VERSION 5.8 ;
BUSBITCHARS "[]" ;
DIVIDERCHAR "/" ;
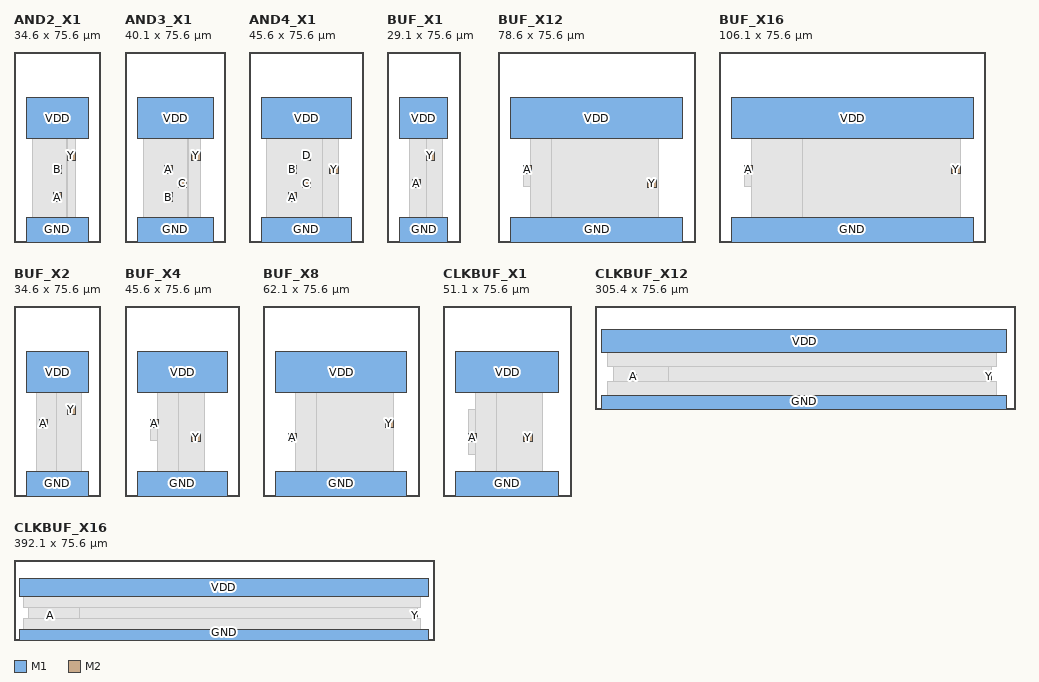
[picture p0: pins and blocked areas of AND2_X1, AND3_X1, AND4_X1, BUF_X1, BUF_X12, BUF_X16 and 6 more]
MACRO AND2_X1
  CLASS CORE ;
  ORIGIN 0 0 ;
  SIZE 34.600 BY 75.600 ;
  SYMMETRY X Y ;
  SITE TR1um_access_site ;
  PIN VDD
    DIRECTION INOUT ;
    USE POWER ;
    PORT
      LAYER M1 ;
        RECT 5.000 41.000 29.600 57.600 ;
    END
  END VDD
  PIN GND
    DIRECTION INOUT ;
    USE GROUND ;
    PORT
      LAYER M1 ;
        RECT 5.000 0.000 29.600 9.800 ;
    END
  END GND
  PIN A
    DIRECTION INPUT ;
    USE SIGNAL ;
    PORT
      LAYER M2 ;
        RECT 15.600 16.100 19.000 19.500 ;
    END
  END A
  PIN B
    DIRECTION INPUT ;
    USE SIGNAL ;
    PORT
      LAYER M2 ;
        RECT 15.600 27.100 19.000 30.500 ;
    END
  END B
  PIN Y
    DIRECTION OUTPUT ;
    USE SIGNAL ;
    PORT
      LAYER M2 ;
        RECT 21.100 32.600 24.500 36.000 ;
    END
  END Y
  OBS
    LAYER M1 ;
      RECT 13.100 6.400 15.700 9.800 ;
    LAYER M1 ;
      RECT 10.600 16.100 19.000 19.500 ;
    LAYER M1 ;
      RECT 14.400 27.100 19.000 35.200 ;
    LAYER M1 ;
      RECT 7.400 6.400 20.900 51.200 ;
    LAYER M1 ;
      RECT 21.100 6.400 24.500 51.200 ;
    LAYER V1 ;
      RECT 16.600 17.100 18.000 18.500 ;
    LAYER V1 ;
      RECT 16.600 28.100 18.000 29.500 ;
    LAYER V1 ;
      RECT 22.100 33.600 23.500 35.000 ;
  END
END AND2_X1
MACRO AND3_X1
  CLASS CORE ;
  ORIGIN 0 0 ;
  SIZE 40.100 BY 75.600 ;
  SYMMETRY X Y ;
  SITE TR1um_access_site ;
  PIN VDD
    DIRECTION INOUT ;
    USE POWER ;
    PORT
      LAYER M1 ;
        RECT 5.000 41.000 35.100 57.600 ;
    END
  END VDD
  PIN GND
    DIRECTION INOUT ;
    USE GROUND ;
    PORT
      LAYER M1 ;
        RECT 5.000 0.000 35.100 9.800 ;
    END
  END GND
  PIN A
    DIRECTION INPUT ;
    USE SIGNAL ;
    PORT
      LAYER M2 ;
        RECT 15.600 27.100 19.000 30.500 ;
    END
  END A
  PIN B
    DIRECTION INPUT ;
    USE SIGNAL ;
    PORT
      LAYER M2 ;
        RECT 15.600 16.100 19.000 19.500 ;
    END
  END B
  PIN C
    DIRECTION INPUT ;
    USE SIGNAL ;
    PORT
      LAYER M2 ;
        RECT 21.100 21.600 24.500 25.000 ;
    END
  END C
  PIN Y
    DIRECTION OUTPUT ;
    USE SIGNAL ;
    PORT
      LAYER M2 ;
        RECT 26.600 32.600 30.000 36.000 ;
    END
  END Y
  OBS
    LAYER M1 ;
      RECT 13.100 6.400 15.700 9.800 ;
    LAYER M1 ;
      RECT 17.100 6.400 19.700 9.800 ;
    LAYER M1 ;
      RECT 12.000 14.600 19.000 19.500 ;
    LAYER M1 ;
      RECT 16.300 21.600 24.500 25.000 ;
    LAYER M1 ;
      RECT 10.700 27.100 19.000 35.800 ;
    LAYER M1 ;
      RECT 7.300 6.400 24.700 51.200 ;
    LAYER M1 ;
      RECT 25.100 6.400 30.000 51.200 ;
    LAYER V1 ;
      RECT 16.600 17.100 18.000 18.500 ;
    LAYER V1 ;
      RECT 22.100 22.600 23.500 24.000 ;
    LAYER V1 ;
      RECT 16.600 28.100 18.000 29.500 ;
    LAYER V1 ;
      RECT 27.600 33.600 29.000 35.000 ;
  END
END AND3_X1
MACRO AND4_X1
  CLASS CORE ;
  ORIGIN 0 0 ;
  SIZE 45.600 BY 75.600 ;
  SYMMETRY X Y ;
  SITE TR1um_access_site ;
  PIN VDD
    DIRECTION INOUT ;
    USE POWER ;
    PORT
      LAYER M1 ;
        RECT 5.000 41.000 40.600 57.600 ;
    END
  END VDD
  PIN GND
    DIRECTION INOUT ;
    USE GROUND ;
    PORT
      LAYER M1 ;
        RECT 5.000 0.000 40.600 9.800 ;
    END
  END GND
  PIN A
    DIRECTION INPUT ;
    USE SIGNAL ;
    PORT
      LAYER M2 ;
        RECT 15.600 16.100 19.000 19.500 ;
    END
  END A
  PIN B
    DIRECTION INPUT ;
    USE SIGNAL ;
    PORT
      LAYER M2 ;
        RECT 15.600 27.100 19.000 30.500 ;
    END
  END B
  PIN C
    DIRECTION INPUT ;
    USE SIGNAL ;
    PORT
      LAYER M2 ;
        RECT 21.100 21.600 24.500 25.000 ;
    END
  END C
  PIN D
    DIRECTION INPUT ;
    USE SIGNAL ;
    PORT
      LAYER M2 ;
        RECT 21.100 32.600 24.500 36.000 ;
    END
  END D
  PIN Y
    DIRECTION OUTPUT ;
    USE SIGNAL ;
    PORT
      LAYER M2 ;
        RECT 32.100 27.100 35.500 30.500 ;
    END
  END Y
  OBS
    LAYER M1 ;
      RECT 13.100 6.400 15.700 9.800 ;
    LAYER M1 ;
      RECT 17.100 6.400 19.700 9.800 ;
    LAYER M1 ;
      RECT 21.100 6.400 23.700 9.800 ;
    LAYER M1 ;
      RECT 10.600 16.100 19.000 23.000 ;
    LAYER M1 ;
      RECT 17.900 21.600 24.500 25.000 ;
    LAYER M1 ;
      RECT 14.400 27.100 19.000 35.200 ;
    LAYER M1 ;
      RECT 21.100 28.400 26.400 36.000 ;
    LAYER M1 ;
      RECT 7.000 6.400 30.500 51.200 ;
    LAYER M1 ;
      RECT 29.100 6.400 35.500 51.200 ;
    LAYER V1 ;
      RECT 16.600 17.100 18.000 18.500 ;
    LAYER V1 ;
      RECT 22.100 22.600 23.500 24.000 ;
    LAYER V1 ;
      RECT 16.600 28.100 18.000 29.500 ;
    LAYER V1 ;
      RECT 33.100 28.100 34.500 29.500 ;
    LAYER V1 ;
      RECT 22.100 33.600 23.500 35.000 ;
  END
END AND4_X1
MACRO BUF_X1
  CLASS CORE ;
  ORIGIN 0 0 ;
  SIZE 29.100 BY 75.600 ;
  SYMMETRY X Y ;
  SITE TR1um_access_site ;
  PIN VDD
    DIRECTION INOUT ;
    USE POWER ;
    PORT
      LAYER M1 ;
        RECT 5.000 41.000 24.100 57.600 ;
    END
  END VDD
  PIN GND
    DIRECTION INOUT ;
    USE GROUND ;
    PORT
      LAYER M1 ;
        RECT 5.000 0.000 24.100 9.800 ;
    END
  END GND
  PIN A
    DIRECTION INPUT ;
    USE SIGNAL ;
    PORT
      LAYER M2 ;
        RECT 10.100 21.600 13.500 25.000 ;
    END
  END A
  PIN Y
    DIRECTION OUTPUT ;
    USE SIGNAL ;
    PORT
      LAYER M2 ;
        RECT 15.600 32.600 19.000 36.000 ;
    END
  END Y
  OBS
    LAYER M1 ;
      RECT 10.100 17.600 14.500 25.000 ;
    LAYER M1 ;
      RECT 9.100 6.400 18.500 51.200 ;
    LAYER M1 ;
      RECT 15.600 6.400 21.900 51.200 ;
    LAYER V1 ;
      RECT 11.100 22.600 12.500 24.000 ;
    LAYER V1 ;
      RECT 16.600 33.600 18.000 35.000 ;
  END
END BUF_X1
MACRO BUF_X12
  CLASS CORE ;
  ORIGIN 0 0 ;
  SIZE 78.600 BY 75.600 ;
  SYMMETRY X Y ;
  SITE TR1um_access_site ;
  PIN VDD
    DIRECTION INOUT ;
    USE POWER ;
    PORT
      LAYER M1 ;
        RECT 5.000 41.000 73.600 57.600 ;
    END
  END VDD
  PIN GND
    DIRECTION INOUT ;
    USE GROUND ;
    PORT
      LAYER M1 ;
        RECT 5.000 0.000 73.600 9.800 ;
    END
  END GND
  PIN A
    DIRECTION INPUT ;
    USE SIGNAL ;
    PORT
      LAYER M2 ;
        RECT 10.100 27.100 13.500 30.500 ;
    END
  END A
  PIN Y
    DIRECTION OUTPUT ;
    USE SIGNAL ;
    PORT
      LAYER M2 ;
        RECT 59.600 21.600 63.000 25.000 ;
    END
  END Y
  OBS
    LAYER M1 ;
      RECT 10.100 22.000 14.500 30.500 ;
    LAYER M1 ;
      RECT 13.100 6.400 59.500 51.200 ;
    LAYER M1 ;
      RECT 21.100 6.400 63.700 51.200 ;
    LAYER V1 ;
      RECT 60.600 22.600 62.000 24.000 ;
    LAYER V1 ;
      RECT 11.100 28.100 12.500 29.500 ;
  END
END BUF_X12
MACRO BUF_X16
  CLASS CORE ;
  ORIGIN 0 0 ;
  SIZE 106.100 BY 75.600 ;
  SYMMETRY X Y ;
  SITE TR1um_access_site ;
  PIN VDD
    DIRECTION INOUT ;
    USE POWER ;
    PORT
      LAYER M1 ;
        RECT 5.000 41.000 101.100 57.600 ;
    END
  END VDD
  PIN GND
    DIRECTION INOUT ;
    USE GROUND ;
    PORT
      LAYER M1 ;
        RECT 5.000 0.000 101.100 9.800 ;
    END
  END GND
  PIN A
    DIRECTION INPUT ;
    USE SIGNAL ;
    PORT
      LAYER M2 ;
        RECT 10.100 27.100 13.500 30.500 ;
    END
  END A
  PIN Y
    DIRECTION OUTPUT ;
    USE SIGNAL ;
    PORT
      LAYER M2 ;
        RECT 92.600 27.100 96.000 30.500 ;
    END
  END Y
  OBS
    LAYER M1 ;
      RECT 10.100 22.000 14.500 30.500 ;
    LAYER M1 ;
      RECT 13.100 6.400 87.700 51.200 ;
    LAYER M1 ;
      RECT 33.100 6.400 96.000 51.200 ;
    LAYER V1 ;
      RECT 11.100 28.100 12.500 29.500 ;
    LAYER V1 ;
      RECT 93.600 28.100 95.000 29.500 ;
  END
END BUF_X16
MACRO BUF_X2
  CLASS CORE ;
  ORIGIN 0 0 ;
  SIZE 34.600 BY 75.600 ;
  SYMMETRY X Y ;
  SITE TR1um_access_site ;
  PIN VDD
    DIRECTION INOUT ;
    USE POWER ;
    PORT
      LAYER M1 ;
        RECT 5.000 41.000 29.600 57.600 ;
    END
  END VDD
  PIN GND
    DIRECTION INOUT ;
    USE GROUND ;
    PORT
      LAYER M1 ;
        RECT 5.000 0.000 29.600 9.800 ;
    END
  END GND
  PIN A
    DIRECTION INPUT ;
    USE SIGNAL ;
    PORT
      LAYER M2 ;
        RECT 10.100 27.100 13.500 30.500 ;
    END
  END A
  PIN Y
    DIRECTION OUTPUT ;
    USE SIGNAL ;
    PORT
      LAYER M2 ;
        RECT 21.100 32.600 24.500 36.000 ;
    END
  END Y
  OBS
    LAYER M1 ;
      RECT 10.100 22.200 14.500 30.500 ;
    LAYER M1 ;
      RECT 9.100 6.400 22.500 51.200 ;
    LAYER M1 ;
      RECT 17.100 6.400 26.900 51.200 ;
    LAYER V1 ;
      RECT 11.100 28.100 12.500 29.500 ;
    LAYER V1 ;
      RECT 22.100 33.600 23.500 35.000 ;
  END
END BUF_X2
MACRO BUF_X4
  CLASS CORE ;
  ORIGIN 0 0 ;
  SIZE 45.600 BY 75.600 ;
  SYMMETRY X Y ;
  SITE TR1um_access_site ;
  PIN VDD
    DIRECTION INOUT ;
    USE POWER ;
    PORT
      LAYER M1 ;
        RECT 5.000 41.000 40.600 57.600 ;
    END
  END VDD
  PIN GND
    DIRECTION INOUT ;
    USE GROUND ;
    PORT
      LAYER M1 ;
        RECT 5.000 0.000 40.600 9.800 ;
    END
  END GND
  PIN A
    DIRECTION INPUT ;
    USE SIGNAL ;
    PORT
      LAYER M2 ;
        RECT 10.100 27.100 13.500 30.500 ;
    END
  END A
  PIN Y
    DIRECTION OUTPUT ;
    USE SIGNAL ;
    PORT
      LAYER M2 ;
        RECT 26.600 21.600 30.000 25.000 ;
    END
  END Y
  OBS
    LAYER M1 ;
      RECT 10.100 22.000 15.400 30.500 ;
    LAYER M1 ;
      RECT 13.100 6.400 22.500 51.200 ;
    LAYER M1 ;
      RECT 21.100 6.400 31.700 51.200 ;
    LAYER V1 ;
      RECT 27.600 22.600 29.000 24.000 ;
    LAYER V1 ;
      RECT 11.100 28.100 12.500 29.500 ;
  END
END BUF_X4
MACRO BUF_X8
  CLASS CORE ;
  ORIGIN 0 0 ;
  SIZE 62.100 BY 75.600 ;
  SYMMETRY X Y ;
  SITE TR1um_access_site ;
  PIN VDD
    DIRECTION INOUT ;
    USE POWER ;
    PORT
      LAYER M1 ;
        RECT 5.000 41.000 57.100 57.600 ;
    END
  END VDD
  PIN GND
    DIRECTION INOUT ;
    USE GROUND ;
    PORT
      LAYER M1 ;
        RECT 5.000 0.000 57.100 9.800 ;
    END
  END GND
  PIN A
    DIRECTION INPUT ;
    USE SIGNAL ;
    PORT
      LAYER M2 ;
        RECT 10.100 21.600 13.500 25.000 ;
    END
  END A
  PIN Y
    DIRECTION OUTPUT ;
    USE SIGNAL ;
    PORT
      LAYER M2 ;
        RECT 48.600 27.100 52.000 30.500 ;
    END
  END Y
  OBS
    LAYER M1 ;
      RECT 10.100 21.600 16.900 25.000 ;
    LAYER M1 ;
      RECT 13.100 6.400 42.500 51.200 ;
    LAYER M1 ;
      RECT 21.100 6.400 52.000 51.200 ;
    LAYER V1 ;
      RECT 11.100 22.600 12.500 24.000 ;
    LAYER V1 ;
      RECT 49.600 28.100 51.000 29.500 ;
  END
END BUF_X8
MACRO CLKBUF_X1
  CLASS CORE ;
  ORIGIN 0 0 ;
  SIZE 51.100 BY 75.600 ;
  SYMMETRY X Y ;
  SITE TR1um_access_site ;
  PIN VDD
    DIRECTION INOUT ;
    USE POWER ;
    PORT
      LAYER M1 ;
        RECT 5.000 41.000 46.100 57.600 ;
    END
  END VDD
  PIN GND
    DIRECTION INOUT ;
    USE GROUND ;
    PORT
      LAYER M1 ;
        RECT 5.000 0.000 46.100 9.800 ;
    END
  END GND
  PIN A
    DIRECTION INPUT ;
    USE SIGNAL ;
    PORT
      LAYER M2 ;
        RECT 10.100 21.600 13.500 25.000 ;
    END
  END A
  PIN Y
    DIRECTION OUTPUT ;
    USE SIGNAL ;
    PORT
      LAYER M2 ;
        RECT 32.100 21.600 35.500 25.000 ;
    END
  END Y
  OBS
    LAYER M1 ;
      RECT 10.100 16.400 15.700 34.400 ;
    LAYER M1 ;
      RECT 13.100 6.400 29.700 51.200 ;
    LAYER M1 ;
      RECT 21.100 6.400 39.700 51.200 ;
    LAYER V1 ;
      RECT 11.100 22.600 12.500 24.000 ;
    LAYER V1 ;
      RECT 33.100 22.600 34.500 24.000 ;
  END
END CLKBUF_X1
MACRO CLKBUF_X12
  CLASS CORE ;
  ORIGIN 0 0 ;
  SIZE 305.400 BY 75.600 ;
  SYMMETRY X Y ;
  SITE TR1um_access_site ;
  PIN VDD
    DIRECTION INOUT ;
    USE POWER ;
    PORT
      LAYER M1 ;
        RECT 5.000 41.000 299.100 57.600 ;
    END
  END VDD
  PIN GND
    DIRECTION INOUT ;
    USE GROUND ;
    PORT
      LAYER M1 ;
        RECT 5.000 0.000 299.100 9.800 ;
    END
  END GND
  PIN A
    DIRECTION INPUT ;
    USE SIGNAL ;
    PORT
      LAYER M2 ;
        RECT 26.600 21.600 30.000 25.000 ;
    END
  END A
  PIN Y
    DIRECTION OUTPUT ;
    USE SIGNAL ;
    PORT
      LAYER M2 ;
        RECT 285.100 21.600 288.500 25.000 ;
    END
  END Y
  OBS
    LAYER M1 ;
      RECT 19.100 16.400 41.700 34.400 ;
    LAYER M1 ;
      RECT 13.100 6.400 281.700 51.200 ;
    LAYER M1 ;
      RECT 53.100 6.400 288.500 51.200 ;
    LAYER V1 ;
      RECT 8.900 4.000 291.900 20.200 ;
    LAYER V1 ;
      RECT 8.900 30.600 291.900 53.600 ;
    LAYER V1 ;
      RECT 164.300 0.000 167.300 2.800 ;
    LAYER V1 ;
      RECT 169.800 0.000 172.800 2.800 ;
    LAYER V1 ;
      RECT 175.300 0.000 178.300 2.800 ;
    LAYER V1 ;
      RECT 180.800 0.000 183.800 2.800 ;
    LAYER V1 ;
      RECT 186.300 0.000 189.300 2.800 ;
    LAYER V1 ;
      RECT 191.800 0.000 194.800 2.800 ;
    LAYER V1 ;
      RECT 197.300 0.000 200.300 2.800 ;
    LAYER V1 ;
      RECT 202.800 0.000 205.800 2.800 ;
    LAYER V1 ;
      RECT 208.300 0.000 211.300 2.800 ;
    LAYER V1 ;
      RECT 213.800 0.000 216.800 2.800 ;
    LAYER V1 ;
      RECT 219.300 0.000 222.300 2.800 ;
    LAYER V1 ;
      RECT 224.800 0.000 227.800 2.800 ;
    LAYER V1 ;
      RECT 230.300 0.000 233.300 2.800 ;
    LAYER V1 ;
      RECT 235.800 0.000 238.800 2.800 ;
    LAYER V1 ;
      RECT 241.300 0.000 244.300 2.800 ;
    LAYER V1 ;
      RECT 246.800 0.000 249.800 2.800 ;
    LAYER V1 ;
      RECT 252.300 0.000 255.300 2.800 ;
    LAYER V1 ;
      RECT 257.800 0.000 260.800 2.800 ;
    LAYER V1 ;
      RECT 263.300 0.000 266.300 2.800 ;
    LAYER V1 ;
      RECT 268.800 0.000 271.800 2.800 ;
    LAYER V1 ;
      RECT 274.300 0.000 277.300 2.800 ;
    LAYER V1 ;
      RECT 279.800 0.000 282.800 2.800 ;
    LAYER V1 ;
      RECT 285.300 0.000 288.300 2.800 ;
    LAYER V1 ;
      RECT 290.800 0.000 293.800 2.800 ;
    LAYER V1 ;
      RECT 296.300 0.000 299.300 2.800 ;
    LAYER V1 ;
      RECT 153.300 0.000 156.300 2.800 ;
    LAYER V1 ;
      RECT 286.100 22.600 287.500 24.000 ;
    LAYER V1 ;
      RECT 158.800 0.000 161.800 2.800 ;
    LAYER V1 ;
      RECT 153.300 54.800 156.300 57.800 ;
    LAYER V1 ;
      RECT 158.800 54.800 161.800 57.800 ;
    LAYER V1 ;
      RECT 164.300 54.800 167.300 57.800 ;
    LAYER V1 ;
      RECT 169.800 54.800 172.800 57.800 ;
    LAYER V1 ;
      RECT 175.300 54.800 178.300 57.800 ;
    LAYER V1 ;
      RECT 180.800 54.800 183.800 57.800 ;
    LAYER V1 ;
      RECT 186.300 54.800 189.300 57.800 ;
    LAYER V1 ;
      RECT 191.800 54.800 194.800 57.800 ;
    LAYER V1 ;
      RECT 197.300 54.800 200.300 57.800 ;
    LAYER V1 ;
      RECT 202.800 54.800 205.800 57.800 ;
    LAYER V1 ;
      RECT 208.300 54.800 211.300 57.800 ;
    LAYER V1 ;
      RECT 213.800 54.800 216.800 57.800 ;
    LAYER V1 ;
      RECT 219.300 54.800 222.300 57.800 ;
    LAYER V1 ;
      RECT 224.800 54.800 227.800 57.800 ;
    LAYER V1 ;
      RECT 230.300 54.800 233.300 57.800 ;
    LAYER V1 ;
      RECT 235.800 54.800 238.800 57.800 ;
    LAYER V1 ;
      RECT 241.300 54.800 244.300 57.800 ;
    LAYER V1 ;
      RECT 246.800 54.800 249.800 57.800 ;
    LAYER V1 ;
      RECT 252.300 54.800 255.300 57.800 ;
    LAYER V1 ;
      RECT 257.800 54.800 260.800 57.800 ;
    LAYER V1 ;
      RECT 263.300 54.800 266.300 57.800 ;
    LAYER V1 ;
      RECT 268.800 54.800 271.800 57.800 ;
    LAYER V1 ;
      RECT 274.300 54.800 277.300 57.800 ;
    LAYER V1 ;
      RECT 279.800 54.800 282.800 57.800 ;
    LAYER V1 ;
      RECT 285.300 54.800 288.300 57.800 ;
    LAYER V1 ;
      RECT 290.800 54.800 293.800 57.800 ;
    LAYER V1 ;
      RECT 296.300 54.800 299.300 57.800 ;
    LAYER V1 ;
      RECT 15.800 0.000 18.800 2.800 ;
    LAYER V1 ;
      RECT 4.800 54.800 7.800 57.800 ;
    LAYER V1 ;
      RECT 10.300 54.800 13.300 57.800 ;
    LAYER V1 ;
      RECT 15.800 54.800 18.800 57.800 ;
    LAYER V1 ;
      RECT 21.300 54.800 24.300 57.800 ;
    LAYER V1 ;
      RECT 26.800 54.800 29.800 57.800 ;
    LAYER V1 ;
      RECT 32.300 54.800 35.300 57.800 ;
    LAYER V1 ;
      RECT 37.800 54.800 40.800 57.800 ;
    LAYER V1 ;
      RECT 43.300 54.800 46.300 57.800 ;
    LAYER V1 ;
      RECT 48.800 54.800 51.800 57.800 ;
    LAYER V1 ;
      RECT 54.300 54.800 57.300 57.800 ;
    LAYER V1 ;
      RECT 59.800 54.800 62.800 57.800 ;
    LAYER V1 ;
      RECT 65.300 54.800 68.300 57.800 ;
    LAYER V1 ;
      RECT 70.800 54.800 73.800 57.800 ;
    LAYER V1 ;
      RECT 76.300 54.800 79.300 57.800 ;
    LAYER V1 ;
      RECT 81.800 54.800 84.800 57.800 ;
    LAYER V1 ;
      RECT 87.300 54.800 90.300 57.800 ;
    LAYER V1 ;
      RECT 92.800 54.800 95.800 57.800 ;
    LAYER V1 ;
      RECT 98.300 54.800 101.300 57.800 ;
    LAYER V1 ;
      RECT 103.800 54.800 106.800 57.800 ;
    LAYER V1 ;
      RECT 109.300 54.800 112.300 57.800 ;
    LAYER V1 ;
      RECT 114.800 54.800 117.800 57.800 ;
    LAYER V1 ;
      RECT 120.300 54.800 123.300 57.800 ;
    LAYER V1 ;
      RECT 125.800 54.800 128.800 57.800 ;
    LAYER V1 ;
      RECT 131.300 54.800 134.300 57.800 ;
    LAYER V1 ;
      RECT 136.800 54.800 139.800 57.800 ;
    LAYER V1 ;
      RECT 142.300 54.800 145.300 57.800 ;
    LAYER V1 ;
      RECT 147.800 54.800 150.800 57.800 ;
    LAYER V1 ;
      RECT 21.300 0.000 24.300 2.800 ;
    LAYER V1 ;
      RECT 26.800 0.000 29.800 2.800 ;
    LAYER V1 ;
      RECT 32.300 0.000 35.300 2.800 ;
    LAYER V1 ;
      RECT 37.800 0.000 40.800 2.800 ;
    LAYER V1 ;
      RECT 43.300 0.000 46.300 2.800 ;
    LAYER V1 ;
      RECT 48.800 0.000 51.800 2.800 ;
    LAYER V1 ;
      RECT 54.300 0.000 57.300 2.800 ;
    LAYER V1 ;
      RECT 59.800 0.000 62.800 2.800 ;
    LAYER V1 ;
      RECT 65.300 0.000 68.300 2.800 ;
    LAYER V1 ;
      RECT 70.800 0.000 73.800 2.800 ;
    LAYER V1 ;
      RECT 76.300 0.000 79.300 2.800 ;
    LAYER V1 ;
      RECT 81.800 0.000 84.800 2.800 ;
    LAYER V1 ;
      RECT 87.300 0.000 90.300 2.800 ;
    LAYER V1 ;
      RECT 92.800 0.000 95.800 2.800 ;
    LAYER V1 ;
      RECT 98.300 0.000 101.300 2.800 ;
    LAYER V1 ;
      RECT 103.800 0.000 106.800 2.800 ;
    LAYER V1 ;
      RECT 109.300 0.000 112.300 2.800 ;
    LAYER V1 ;
      RECT 114.800 0.000 117.800 2.800 ;
    LAYER V1 ;
      RECT 120.300 0.000 123.300 2.800 ;
    LAYER V1 ;
      RECT 125.800 0.000 128.800 2.800 ;
    LAYER V1 ;
      RECT 131.300 0.000 134.300 2.800 ;
    LAYER V1 ;
      RECT 136.800 0.000 139.800 2.800 ;
    LAYER V1 ;
      RECT 142.300 0.000 145.300 2.800 ;
    LAYER V1 ;
      RECT 147.800 0.000 150.800 2.800 ;
    LAYER V1 ;
      RECT 4.800 0.000 7.800 2.800 ;
    LAYER V1 ;
      RECT 27.600 22.600 29.000 24.000 ;
    LAYER V1 ;
      RECT 10.300 0.000 13.300 2.800 ;
  END
END CLKBUF_X12
MACRO CLKBUF_X16
  CLASS CORE ;
  ORIGIN 0 0 ;
  SIZE 392.100 BY 75.600 ;
  SYMMETRY X Y ;
  SITE TR1um_access_site ;
  PIN VDD
    DIRECTION INOUT ;
    USE POWER ;
    PORT
      LAYER M1 ;
        RECT 5.000 41.000 387.100 57.600 ;
    END
  END VDD
  PIN GND
    DIRECTION INOUT ;
    USE GROUND ;
    PORT
      LAYER M1 ;
        RECT 5.000 0.000 387.100 9.800 ;
    END
  END GND
  PIN A
    DIRECTION INPUT ;
    USE SIGNAL ;
    PORT
      LAYER M2 ;
        RECT 32.100 21.600 35.500 25.000 ;
    END
  END A
  PIN Y
    DIRECTION OUTPUT ;
    USE SIGNAL ;
    PORT
      LAYER M2 ;
        RECT 373.100 21.600 376.500 25.000 ;
    END
  END Y
  OBS
    LAYER M1 ;
      RECT 17.100 16.400 51.700 34.400 ;
    LAYER M1 ;
      RECT 13.100 6.400 369.700 51.200 ;
    LAYER M1 ;
      RECT 61.100 6.400 376.500 51.200 ;
    LAYER V1 ;
      RECT 8.900 4.000 379.900 20.200 ;
    LAYER V1 ;
      RECT 8.900 30.600 379.900 53.600 ;
    LAYER V1 ;
      RECT 208.300 0.000 211.300 2.800 ;
    LAYER V1 ;
      RECT 213.800 0.000 216.800 2.800 ;
    LAYER V1 ;
      RECT 219.300 0.000 222.300 2.800 ;
    LAYER V1 ;
      RECT 224.800 0.000 227.800 2.800 ;
    LAYER V1 ;
      RECT 230.300 0.000 233.300 2.800 ;
    LAYER V1 ;
      RECT 235.800 0.000 238.800 2.800 ;
    LAYER V1 ;
      RECT 241.300 0.000 244.300 2.800 ;
    LAYER V1 ;
      RECT 246.800 0.000 249.800 2.800 ;
    LAYER V1 ;
      RECT 252.300 0.000 255.300 2.800 ;
    LAYER V1 ;
      RECT 257.800 0.000 260.800 2.800 ;
    LAYER V1 ;
      RECT 263.300 0.000 266.300 2.800 ;
    LAYER V1 ;
      RECT 268.800 0.000 271.800 2.800 ;
    LAYER V1 ;
      RECT 274.300 0.000 277.300 2.800 ;
    LAYER V1 ;
      RECT 279.800 0.000 282.800 2.800 ;
    LAYER V1 ;
      RECT 285.300 0.000 288.300 2.800 ;
    LAYER V1 ;
      RECT 290.800 0.000 293.800 2.800 ;
    LAYER V1 ;
      RECT 296.300 0.000 299.300 2.800 ;
    LAYER V1 ;
      RECT 301.800 0.000 304.800 2.800 ;
    LAYER V1 ;
      RECT 307.300 0.000 310.300 2.800 ;
    LAYER V1 ;
      RECT 312.800 0.000 315.800 2.800 ;
    LAYER V1 ;
      RECT 318.300 0.000 321.300 2.800 ;
    LAYER V1 ;
      RECT 323.800 0.000 326.800 2.800 ;
    LAYER V1 ;
      RECT 329.300 0.000 332.300 2.800 ;
    LAYER V1 ;
      RECT 334.800 0.000 337.800 2.800 ;
    LAYER V1 ;
      RECT 340.300 0.000 343.300 2.800 ;
    LAYER V1 ;
      RECT 345.800 0.000 348.800 2.800 ;
    LAYER V1 ;
      RECT 351.300 0.000 354.300 2.800 ;
    LAYER V1 ;
      RECT 356.800 0.000 359.800 2.800 ;
    LAYER V1 ;
      RECT 362.300 0.000 365.300 2.800 ;
    LAYER V1 ;
      RECT 367.800 0.000 370.800 2.800 ;
    LAYER V1 ;
      RECT 373.300 0.000 376.300 2.800 ;
    LAYER V1 ;
      RECT 378.800 0.000 381.800 2.800 ;
    LAYER V1 ;
      RECT 384.300 0.000 387.300 2.800 ;
    LAYER V1 ;
      RECT 197.300 0.000 200.300 2.800 ;
    LAYER V1 ;
      RECT 374.100 22.600 375.500 24.000 ;
    LAYER V1 ;
      RECT 202.800 0.000 205.800 2.800 ;
    LAYER V1 ;
      RECT 197.300 54.800 200.300 57.800 ;
    LAYER V1 ;
      RECT 202.800 54.800 205.800 57.800 ;
    LAYER V1 ;
      RECT 208.300 54.800 211.300 57.800 ;
    LAYER V1 ;
      RECT 213.800 54.800 216.800 57.800 ;
    LAYER V1 ;
      RECT 219.300 54.800 222.300 57.800 ;
    LAYER V1 ;
      RECT 224.800 54.800 227.800 57.800 ;
    LAYER V1 ;
      RECT 230.300 54.800 233.300 57.800 ;
    LAYER V1 ;
      RECT 235.800 54.800 238.800 57.800 ;
    LAYER V1 ;
      RECT 241.300 54.800 244.300 57.800 ;
    LAYER V1 ;
      RECT 246.800 54.800 249.800 57.800 ;
    LAYER V1 ;
      RECT 252.300 54.800 255.300 57.800 ;
    LAYER V1 ;
      RECT 257.800 54.800 260.800 57.800 ;
    LAYER V1 ;
      RECT 263.300 54.800 266.300 57.800 ;
    LAYER V1 ;
      RECT 268.800 54.800 271.800 57.800 ;
    LAYER V1 ;
      RECT 274.300 54.800 277.300 57.800 ;
    LAYER V1 ;
      RECT 279.800 54.800 282.800 57.800 ;
    LAYER V1 ;
      RECT 285.300 54.800 288.300 57.800 ;
    LAYER V1 ;
      RECT 290.800 54.800 293.800 57.800 ;
    LAYER V1 ;
      RECT 296.300 54.800 299.300 57.800 ;
    LAYER V1 ;
      RECT 301.800 54.800 304.800 57.800 ;
    LAYER V1 ;
      RECT 307.300 54.800 310.300 57.800 ;
    LAYER V1 ;
      RECT 312.800 54.800 315.800 57.800 ;
    LAYER V1 ;
      RECT 318.300 54.800 321.300 57.800 ;
    LAYER V1 ;
      RECT 323.800 54.800 326.800 57.800 ;
    LAYER V1 ;
      RECT 329.300 54.800 332.300 57.800 ;
    LAYER V1 ;
      RECT 334.800 54.800 337.800 57.800 ;
    LAYER V1 ;
      RECT 340.300 54.800 343.300 57.800 ;
    LAYER V1 ;
      RECT 345.800 54.800 348.800 57.800 ;
    LAYER V1 ;
      RECT 351.300 54.800 354.300 57.800 ;
    LAYER V1 ;
      RECT 356.800 54.800 359.800 57.800 ;
    LAYER V1 ;
      RECT 362.300 54.800 365.300 57.800 ;
    LAYER V1 ;
      RECT 367.800 54.800 370.800 57.800 ;
    LAYER V1 ;
      RECT 373.300 54.800 376.300 57.800 ;
    LAYER V1 ;
      RECT 378.800 54.800 381.800 57.800 ;
    LAYER V1 ;
      RECT 384.300 54.800 387.300 57.800 ;
    LAYER V1 ;
      RECT 15.800 0.000 18.800 2.800 ;
    LAYER V1 ;
      RECT 4.800 54.800 7.800 57.800 ;
    LAYER V1 ;
      RECT 10.300 54.800 13.300 57.800 ;
    LAYER V1 ;
      RECT 15.800 54.800 18.800 57.800 ;
    LAYER V1 ;
      RECT 21.300 54.800 24.300 57.800 ;
    LAYER V1 ;
      RECT 26.800 54.800 29.800 57.800 ;
    LAYER V1 ;
      RECT 32.300 54.800 35.300 57.800 ;
    LAYER V1 ;
      RECT 37.800 54.800 40.800 57.800 ;
    LAYER V1 ;
      RECT 43.300 54.800 46.300 57.800 ;
    LAYER V1 ;
      RECT 48.800 54.800 51.800 57.800 ;
    LAYER V1 ;
      RECT 54.300 54.800 57.300 57.800 ;
    LAYER V1 ;
      RECT 59.800 54.800 62.800 57.800 ;
    LAYER V1 ;
      RECT 65.300 54.800 68.300 57.800 ;
    LAYER V1 ;
      RECT 70.800 54.800 73.800 57.800 ;
    LAYER V1 ;
      RECT 76.300 54.800 79.300 57.800 ;
    LAYER V1 ;
      RECT 81.800 54.800 84.800 57.800 ;
    LAYER V1 ;
      RECT 87.300 54.800 90.300 57.800 ;
    LAYER V1 ;
      RECT 92.800 54.800 95.800 57.800 ;
    LAYER V1 ;
      RECT 98.300 54.800 101.300 57.800 ;
    LAYER V1 ;
      RECT 103.800 54.800 106.800 57.800 ;
    LAYER V1 ;
      RECT 109.300 54.800 112.300 57.800 ;
    LAYER V1 ;
      RECT 114.800 54.800 117.800 57.800 ;
    LAYER V1 ;
      RECT 120.300 54.800 123.300 57.800 ;
    LAYER V1 ;
      RECT 125.800 54.800 128.800 57.800 ;
    LAYER V1 ;
      RECT 131.300 54.800 134.300 57.800 ;
    LAYER V1 ;
      RECT 136.800 54.800 139.800 57.800 ;
    LAYER V1 ;
      RECT 142.300 54.800 145.300 57.800 ;
    LAYER V1 ;
      RECT 147.800 54.800 150.800 57.800 ;
    LAYER V1 ;
      RECT 153.300 54.800 156.300 57.800 ;
    LAYER V1 ;
      RECT 158.800 54.800 161.800 57.800 ;
    LAYER V1 ;
      RECT 164.300 54.800 167.300 57.800 ;
    LAYER V1 ;
      RECT 169.800 54.800 172.800 57.800 ;
    LAYER V1 ;
      RECT 175.300 54.800 178.300 57.800 ;
    LAYER V1 ;
      RECT 180.800 54.800 183.800 57.800 ;
    LAYER V1 ;
      RECT 186.300 54.800 189.300 57.800 ;
    LAYER V1 ;
      RECT 191.800 54.800 194.800 57.800 ;
    LAYER V1 ;
      RECT 21.300 0.000 24.300 2.800 ;
    LAYER V1 ;
      RECT 26.800 0.000 29.800 2.800 ;
    LAYER V1 ;
      RECT 32.300 0.000 35.300 2.800 ;
    LAYER V1 ;
      RECT 37.800 0.000 40.800 2.800 ;
    LAYER V1 ;
      RECT 43.300 0.000 46.300 2.800 ;
    LAYER V1 ;
      RECT 48.800 0.000 51.800 2.800 ;
    LAYER V1 ;
      RECT 54.300 0.000 57.300 2.800 ;
    LAYER V1 ;
      RECT 59.800 0.000 62.800 2.800 ;
    LAYER V1 ;
      RECT 65.300 0.000 68.300 2.800 ;
    LAYER V1 ;
      RECT 70.800 0.000 73.800 2.800 ;
    LAYER V1 ;
      RECT 76.300 0.000 79.300 2.800 ;
    LAYER V1 ;
      RECT 81.800 0.000 84.800 2.800 ;
    LAYER V1 ;
      RECT 87.300 0.000 90.300 2.800 ;
    LAYER V1 ;
      RECT 92.800 0.000 95.800 2.800 ;
    LAYER V1 ;
      RECT 98.300 0.000 101.300 2.800 ;
    LAYER V1 ;
      RECT 103.800 0.000 106.800 2.800 ;
    LAYER V1 ;
      RECT 109.300 0.000 112.300 2.800 ;
    LAYER V1 ;
      RECT 114.800 0.000 117.800 2.800 ;
    LAYER V1 ;
      RECT 120.300 0.000 123.300 2.800 ;
    LAYER V1 ;
      RECT 125.800 0.000 128.800 2.800 ;
    LAYER V1 ;
      RECT 131.300 0.000 134.300 2.800 ;
    LAYER V1 ;
      RECT 136.800 0.000 139.800 2.800 ;
    LAYER V1 ;
      RECT 142.300 0.000 145.300 2.800 ;
    LAYER V1 ;
      RECT 147.800 0.000 150.800 2.800 ;
    LAYER V1 ;
      RECT 153.300 0.000 156.300 2.800 ;
    LAYER V1 ;
      RECT 158.800 0.000 161.800 2.800 ;
    LAYER V1 ;
      RECT 164.300 0.000 167.300 2.800 ;
    LAYER V1 ;
      RECT 169.800 0.000 172.800 2.800 ;
    LAYER V1 ;
      RECT 175.300 0.000 178.300 2.800 ;
    LAYER V1 ;
      RECT 180.800 0.000 183.800 2.800 ;
    LAYER V1 ;
      RECT 186.300 0.000 189.300 2.800 ;
    LAYER V1 ;
      RECT 191.800 0.000 194.800 2.800 ;
    LAYER V1 ;
      RECT 4.800 0.000 7.800 2.800 ;
    LAYER V1 ;
      RECT 33.100 22.600 34.500 24.000 ;
    LAYER V1 ;
      RECT 10.300 0.000 13.300 2.800 ;
  END
END CLKBUF_X16
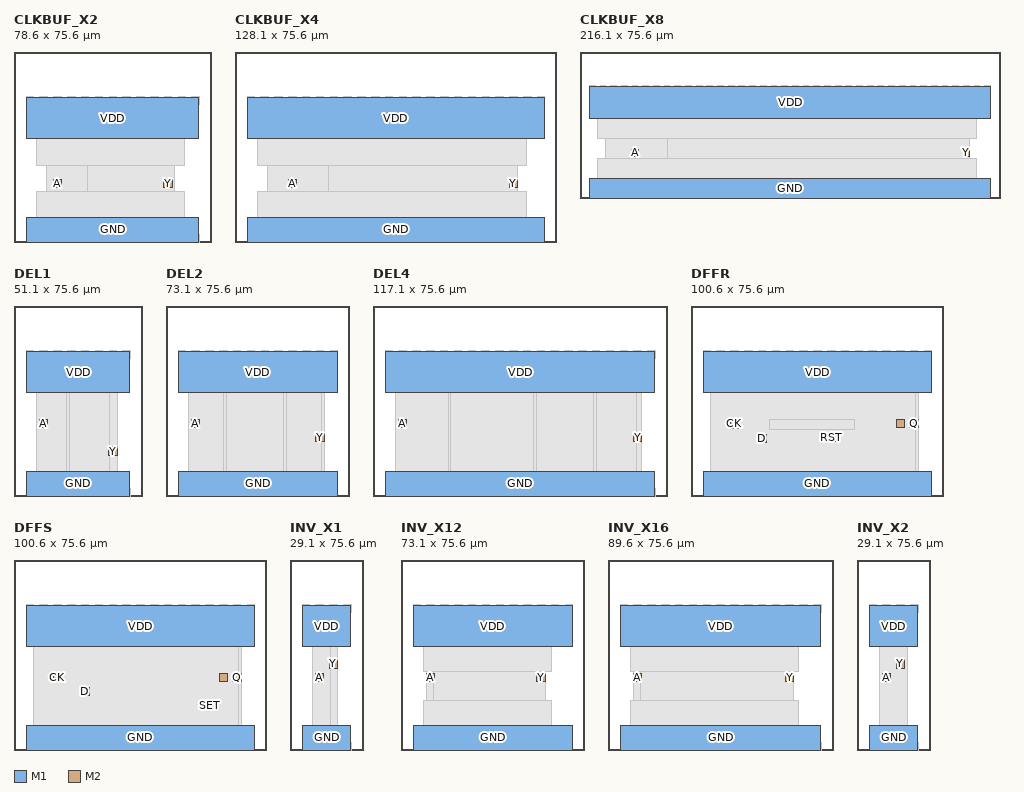
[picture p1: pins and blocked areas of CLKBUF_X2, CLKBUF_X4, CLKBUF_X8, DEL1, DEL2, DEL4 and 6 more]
MACRO CLKBUF_X2
  CLASS CORE ;
  ORIGIN 0 0 ;
  SIZE 78.600 BY 75.600 ;
  SYMMETRY X Y ;
  SITE TR1um_access_site ;
  PIN VDD
    DIRECTION INOUT ;
    USE POWER ;
    PORT
      LAYER M1 ;
        RECT 5.000 41.000 73.600 57.600 ;
    END
  END VDD
  PIN GND
    DIRECTION INOUT ;
    USE GROUND ;
    PORT
      LAYER M1 ;
        RECT 5.000 0.000 73.600 9.800 ;
    END
  END GND
  PIN A
    DIRECTION INPUT ;
    USE SIGNAL ;
    PORT
      LAYER M2 ;
        RECT 15.600 21.600 19.000 25.000 ;
    END
  END A
  PIN Y
    DIRECTION OUTPUT ;
    USE SIGNAL ;
    PORT
      LAYER M2 ;
        RECT 59.600 21.600 63.000 25.000 ;
    END
  END Y
  OBS
    LAYER M1 ;
      RECT 15.600 16.400 19.700 34.400 ;
    LAYER M1 ;
      RECT 13.100 6.400 57.700 51.200 ;
    LAYER M1 ;
      RECT 29.100 6.400 63.700 51.200 ;
    LAYER V1 ;
      RECT 4.800 0.000 7.800 2.800 ;
    LAYER V1 ;
      RECT 10.300 0.000 13.300 2.800 ;
    LAYER V1 ;
      RECT 15.800 0.000 18.800 2.800 ;
    LAYER V1 ;
      RECT 21.300 0.000 24.300 2.800 ;
    LAYER V1 ;
      RECT 26.800 0.000 29.800 2.800 ;
    LAYER V1 ;
      RECT 32.300 0.000 35.300 2.800 ;
    LAYER V1 ;
      RECT 37.800 0.000 40.800 2.800 ;
    LAYER V1 ;
      RECT 43.300 0.000 46.300 2.800 ;
    LAYER V1 ;
      RECT 48.800 0.000 51.800 2.800 ;
    LAYER V1 ;
      RECT 54.300 0.000 57.300 2.800 ;
    LAYER V1 ;
      RECT 59.800 0.000 62.800 2.800 ;
    LAYER V1 ;
      RECT 65.300 0.000 68.300 2.800 ;
    LAYER V1 ;
      RECT 70.800 0.000 73.800 2.800 ;
    LAYER V1 ;
      RECT 8.900 4.000 67.900 20.200 ;
    LAYER V1 ;
      RECT 16.600 22.600 18.000 24.000 ;
    LAYER V1 ;
      RECT 60.600 22.600 62.000 24.000 ;
    LAYER V1 ;
      RECT 8.900 30.600 67.900 53.600 ;
    LAYER V1 ;
      RECT 4.800 54.800 7.800 57.800 ;
    LAYER V1 ;
      RECT 10.300 54.800 13.300 57.800 ;
    LAYER V1 ;
      RECT 15.800 54.800 18.800 57.800 ;
    LAYER V1 ;
      RECT 21.300 54.800 24.300 57.800 ;
    LAYER V1 ;
      RECT 26.800 54.800 29.800 57.800 ;
    LAYER V1 ;
      RECT 32.300 54.800 35.300 57.800 ;
    LAYER V1 ;
      RECT 37.800 54.800 40.800 57.800 ;
    LAYER V1 ;
      RECT 43.300 54.800 46.300 57.800 ;
    LAYER V1 ;
      RECT 48.800 54.800 51.800 57.800 ;
    LAYER V1 ;
      RECT 54.300 54.800 57.300 57.800 ;
    LAYER V1 ;
      RECT 59.800 54.800 62.800 57.800 ;
    LAYER V1 ;
      RECT 65.300 54.800 68.300 57.800 ;
    LAYER V1 ;
      RECT 70.800 54.800 73.800 57.800 ;
  END
END CLKBUF_X2
MACRO CLKBUF_X4
  CLASS CORE ;
  ORIGIN 0 0 ;
  SIZE 128.100 BY 75.600 ;
  SYMMETRY X Y ;
  SITE TR1um_access_site ;
  PIN VDD
    DIRECTION INOUT ;
    USE POWER ;
    PORT
      LAYER M1 ;
        RECT 5.000 41.000 123.100 57.600 ;
    END
  END VDD
  PIN GND
    DIRECTION INOUT ;
    USE GROUND ;
    PORT
      LAYER M1 ;
        RECT 5.000 0.000 123.100 9.800 ;
    END
  END GND
  PIN A
    DIRECTION INPUT ;
    USE SIGNAL ;
    PORT
      LAYER M2 ;
        RECT 21.100 21.600 24.500 25.000 ;
    END
  END A
  PIN Y
    DIRECTION OUTPUT ;
    USE SIGNAL ;
    PORT
      LAYER M2 ;
        RECT 109.100 21.600 112.500 25.000 ;
    END
  END Y
  OBS
    LAYER M1 ;
      RECT 15.100 16.400 29.700 34.400 ;
    LAYER M1 ;
      RECT 13.100 6.400 105.700 51.200 ;
    LAYER M1 ;
      RECT 37.100 6.400 112.500 51.200 ;
    LAYER V1 ;
      RECT 4.800 0.000 7.800 2.800 ;
    LAYER V1 ;
      RECT 10.300 0.000 13.300 2.800 ;
    LAYER V1 ;
      RECT 15.800 0.000 18.800 2.800 ;
    LAYER V1 ;
      RECT 21.300 0.000 24.300 2.800 ;
    LAYER V1 ;
      RECT 26.800 0.000 29.800 2.800 ;
    LAYER V1 ;
      RECT 32.300 0.000 35.300 2.800 ;
    LAYER V1 ;
      RECT 37.800 0.000 40.800 2.800 ;
    LAYER V1 ;
      RECT 43.300 0.000 46.300 2.800 ;
    LAYER V1 ;
      RECT 48.800 0.000 51.800 2.800 ;
    LAYER V1 ;
      RECT 54.300 0.000 57.300 2.800 ;
    LAYER V1 ;
      RECT 59.800 0.000 62.800 2.800 ;
    LAYER V1 ;
      RECT 65.300 0.000 68.300 2.800 ;
    LAYER V1 ;
      RECT 70.800 0.000 73.800 2.800 ;
    LAYER V1 ;
      RECT 76.300 0.000 79.300 2.800 ;
    LAYER V1 ;
      RECT 81.800 0.000 84.800 2.800 ;
    LAYER V1 ;
      RECT 87.300 0.000 90.300 2.800 ;
    LAYER V1 ;
      RECT 92.800 0.000 95.800 2.800 ;
    LAYER V1 ;
      RECT 98.300 0.000 101.300 2.800 ;
    LAYER V1 ;
      RECT 103.800 0.000 106.800 2.800 ;
    LAYER V1 ;
      RECT 109.300 0.000 112.300 2.800 ;
    LAYER V1 ;
      RECT 114.800 0.000 117.800 2.800 ;
    LAYER V1 ;
      RECT 120.300 0.000 123.300 2.800 ;
    LAYER V1 ;
      RECT 8.900 4.000 115.900 20.200 ;
    LAYER V1 ;
      RECT 22.100 22.600 23.500 24.000 ;
    LAYER V1 ;
      RECT 110.100 22.600 111.500 24.000 ;
    LAYER V1 ;
      RECT 8.900 30.600 115.900 53.600 ;
    LAYER V1 ;
      RECT 4.800 54.800 7.800 57.800 ;
    LAYER V1 ;
      RECT 10.300 54.800 13.300 57.800 ;
    LAYER V1 ;
      RECT 15.800 54.800 18.800 57.800 ;
    LAYER V1 ;
      RECT 21.300 54.800 24.300 57.800 ;
    LAYER V1 ;
      RECT 26.800 54.800 29.800 57.800 ;
    LAYER V1 ;
      RECT 32.300 54.800 35.300 57.800 ;
    LAYER V1 ;
      RECT 37.800 54.800 40.800 57.800 ;
    LAYER V1 ;
      RECT 43.300 54.800 46.300 57.800 ;
    LAYER V1 ;
      RECT 48.800 54.800 51.800 57.800 ;
    LAYER V1 ;
      RECT 54.300 54.800 57.300 57.800 ;
    LAYER V1 ;
      RECT 59.800 54.800 62.800 57.800 ;
    LAYER V1 ;
      RECT 65.300 54.800 68.300 57.800 ;
    LAYER V1 ;
      RECT 70.800 54.800 73.800 57.800 ;
    LAYER V1 ;
      RECT 76.300 54.800 79.300 57.800 ;
    LAYER V1 ;
      RECT 81.800 54.800 84.800 57.800 ;
    LAYER V1 ;
      RECT 87.300 54.800 90.300 57.800 ;
    LAYER V1 ;
      RECT 92.800 54.800 95.800 57.800 ;
    LAYER V1 ;
      RECT 98.300 54.800 101.300 57.800 ;
    LAYER V1 ;
      RECT 103.800 54.800 106.800 57.800 ;
    LAYER V1 ;
      RECT 109.300 54.800 112.300 57.800 ;
    LAYER V1 ;
      RECT 114.800 54.800 117.800 57.800 ;
    LAYER V1 ;
      RECT 120.300 54.800 123.300 57.800 ;
  END
END CLKBUF_X4
MACRO CLKBUF_X8
  CLASS CORE ;
  ORIGIN 0 0 ;
  SIZE 216.100 BY 75.600 ;
  SYMMETRY X Y ;
  SITE TR1um_access_site ;
  PIN VDD
    DIRECTION INOUT ;
    USE POWER ;
    PORT
      LAYER M1 ;
        RECT 5.000 41.000 211.100 57.600 ;
    END
  END VDD
  PIN GND
    DIRECTION INOUT ;
    USE GROUND ;
    PORT
      LAYER M1 ;
        RECT 5.000 0.000 211.100 9.800 ;
    END
  END GND
  PIN A
    DIRECTION INPUT ;
    USE SIGNAL ;
    PORT
      LAYER M2 ;
        RECT 26.600 21.600 30.000 25.000 ;
    END
  END A
  PIN Y
    DIRECTION OUTPUT ;
    USE SIGNAL ;
    PORT
      LAYER M2 ;
        RECT 197.100 21.600 200.500 25.000 ;
    END
  END Y
  OBS
    LAYER M1 ;
      RECT 17.100 16.400 35.700 34.400 ;
    LAYER M1 ;
      RECT 13.100 6.400 193.700 51.200 ;
    LAYER M1 ;
      RECT 45.100 6.400 200.500 51.200 ;
    LAYER V1 ;
      RECT 4.800 0.000 7.800 2.800 ;
    LAYER V1 ;
      RECT 10.300 0.000 13.300 2.800 ;
    LAYER V1 ;
      RECT 15.800 0.000 18.800 2.800 ;
    LAYER V1 ;
      RECT 21.300 0.000 24.300 2.800 ;
    LAYER V1 ;
      RECT 26.800 0.000 29.800 2.800 ;
    LAYER V1 ;
      RECT 32.300 0.000 35.300 2.800 ;
    LAYER V1 ;
      RECT 37.800 0.000 40.800 2.800 ;
    LAYER V1 ;
      RECT 43.300 0.000 46.300 2.800 ;
    LAYER V1 ;
      RECT 48.800 0.000 51.800 2.800 ;
    LAYER V1 ;
      RECT 54.300 0.000 57.300 2.800 ;
    LAYER V1 ;
      RECT 59.800 0.000 62.800 2.800 ;
    LAYER V1 ;
      RECT 65.300 0.000 68.300 2.800 ;
    LAYER V1 ;
      RECT 70.800 0.000 73.800 2.800 ;
    LAYER V1 ;
      RECT 76.300 0.000 79.300 2.800 ;
    LAYER V1 ;
      RECT 81.800 0.000 84.800 2.800 ;
    LAYER V1 ;
      RECT 87.300 0.000 90.300 2.800 ;
    LAYER V1 ;
      RECT 92.800 0.000 95.800 2.800 ;
    LAYER V1 ;
      RECT 98.300 0.000 101.300 2.800 ;
    LAYER V1 ;
      RECT 103.800 0.000 106.800 2.800 ;
    LAYER V1 ;
      RECT 109.300 0.000 112.300 2.800 ;
    LAYER V1 ;
      RECT 114.800 0.000 117.800 2.800 ;
    LAYER V1 ;
      RECT 120.300 0.000 123.300 2.800 ;
    LAYER V1 ;
      RECT 125.800 0.000 128.800 2.800 ;
    LAYER V1 ;
      RECT 131.300 0.000 134.300 2.800 ;
    LAYER V1 ;
      RECT 136.800 0.000 139.800 2.800 ;
    LAYER V1 ;
      RECT 142.300 0.000 145.300 2.800 ;
    LAYER V1 ;
      RECT 147.800 0.000 150.800 2.800 ;
    LAYER V1 ;
      RECT 153.300 0.000 156.300 2.800 ;
    LAYER V1 ;
      RECT 158.800 0.000 161.800 2.800 ;
    LAYER V1 ;
      RECT 164.300 0.000 167.300 2.800 ;
    LAYER V1 ;
      RECT 169.800 0.000 172.800 2.800 ;
    LAYER V1 ;
      RECT 175.300 0.000 178.300 2.800 ;
    LAYER V1 ;
      RECT 180.800 0.000 183.800 2.800 ;
    LAYER V1 ;
      RECT 186.300 0.000 189.300 2.800 ;
    LAYER V1 ;
      RECT 191.800 0.000 194.800 2.800 ;
    LAYER V1 ;
      RECT 197.300 0.000 200.300 2.800 ;
    LAYER V1 ;
      RECT 202.800 0.000 205.800 2.800 ;
    LAYER V1 ;
      RECT 208.300 0.000 211.300 2.800 ;
    LAYER V1 ;
      RECT 8.900 4.000 203.900 20.200 ;
    LAYER V1 ;
      RECT 27.600 22.600 29.000 24.000 ;
    LAYER V1 ;
      RECT 198.100 22.600 199.500 24.000 ;
    LAYER V1 ;
      RECT 8.900 30.600 203.900 53.600 ;
    LAYER V1 ;
      RECT 4.800 54.800 7.800 57.800 ;
    LAYER V1 ;
      RECT 10.300 54.800 13.300 57.800 ;
    LAYER V1 ;
      RECT 15.800 54.800 18.800 57.800 ;
    LAYER V1 ;
      RECT 21.300 54.800 24.300 57.800 ;
    LAYER V1 ;
      RECT 26.800 54.800 29.800 57.800 ;
    LAYER V1 ;
      RECT 32.300 54.800 35.300 57.800 ;
    LAYER V1 ;
      RECT 37.800 54.800 40.800 57.800 ;
    LAYER V1 ;
      RECT 43.300 54.800 46.300 57.800 ;
    LAYER V1 ;
      RECT 48.800 54.800 51.800 57.800 ;
    LAYER V1 ;
      RECT 54.300 54.800 57.300 57.800 ;
    LAYER V1 ;
      RECT 59.800 54.800 62.800 57.800 ;
    LAYER V1 ;
      RECT 65.300 54.800 68.300 57.800 ;
    LAYER V1 ;
      RECT 70.800 54.800 73.800 57.800 ;
    LAYER V1 ;
      RECT 76.300 54.800 79.300 57.800 ;
    LAYER V1 ;
      RECT 81.800 54.800 84.800 57.800 ;
    LAYER V1 ;
      RECT 87.300 54.800 90.300 57.800 ;
    LAYER V1 ;
      RECT 92.800 54.800 95.800 57.800 ;
    LAYER V1 ;
      RECT 98.300 54.800 101.300 57.800 ;
    LAYER V1 ;
      RECT 103.800 54.800 106.800 57.800 ;
    LAYER V1 ;
      RECT 109.300 54.800 112.300 57.800 ;
    LAYER V1 ;
      RECT 114.800 54.800 117.800 57.800 ;
    LAYER V1 ;
      RECT 120.300 54.800 123.300 57.800 ;
    LAYER V1 ;
      RECT 125.800 54.800 128.800 57.800 ;
    LAYER V1 ;
      RECT 131.300 54.800 134.300 57.800 ;
    LAYER V1 ;
      RECT 136.800 54.800 139.800 57.800 ;
    LAYER V1 ;
      RECT 142.300 54.800 145.300 57.800 ;
    LAYER V1 ;
      RECT 147.800 54.800 150.800 57.800 ;
    LAYER V1 ;
      RECT 153.300 54.800 156.300 57.800 ;
    LAYER V1 ;
      RECT 158.800 54.800 161.800 57.800 ;
    LAYER V1 ;
      RECT 164.300 54.800 167.300 57.800 ;
    LAYER V1 ;
      RECT 169.800 54.800 172.800 57.800 ;
    LAYER V1 ;
      RECT 175.300 54.800 178.300 57.800 ;
    LAYER V1 ;
      RECT 180.800 54.800 183.800 57.800 ;
    LAYER V1 ;
      RECT 186.300 54.800 189.300 57.800 ;
    LAYER V1 ;
      RECT 191.800 54.800 194.800 57.800 ;
    LAYER V1 ;
      RECT 197.300 54.800 200.300 57.800 ;
    LAYER V1 ;
      RECT 202.800 54.800 205.800 57.800 ;
    LAYER V1 ;
      RECT 208.300 54.800 211.300 57.800 ;
  END
END CLKBUF_X8
MACRO DEL1
  CLASS CORE ;
  ORIGIN 0 0 ;
  SIZE 51.100 BY 75.600 ;
  SYMMETRY X Y ;
  SITE TR1um_access_site ;
  PIN VDD
    DIRECTION INOUT ;
    USE POWER ;
    PORT
      LAYER M1 ;
        RECT 5.000 41.000 46.100 57.600 ;
    END
  END VDD
  PIN GND
    DIRECTION INOUT ;
    USE GROUND ;
    PORT
      LAYER M1 ;
        RECT 5.000 0.000 46.100 9.800 ;
    END
  END GND
  PIN A
    DIRECTION INPUT ;
    USE SIGNAL ;
    PORT
      LAYER M2 ;
        RECT 10.100 27.100 13.500 30.500 ;
    END
  END A
  PIN Y
    DIRECTION OUTPUT ;
    USE SIGNAL ;
    PORT
      LAYER M2 ;
        RECT 37.600 16.100 41.000 19.500 ;
    END
  END Y
  OBS
    LAYER M1 ;
      RECT 10.100 22.000 13.700 30.500 ;
    LAYER M1 ;
      RECT 9.100 6.400 16.900 51.200 ;
    LAYER M1 ;
      RECT 18.100 6.400 27.200 51.200 ;
    LAYER M1 ;
      RECT 22.100 6.400 31.600 51.200 ;
    LAYER M1 ;
      RECT 31.100 6.400 41.000 51.200 ;
    LAYER V1 ;
      RECT 4.800 0.000 7.800 2.800 ;
    LAYER V1 ;
      RECT 10.300 0.000 13.300 2.800 ;
    LAYER V1 ;
      RECT 15.800 0.000 18.800 2.800 ;
    LAYER V1 ;
      RECT 21.300 0.000 24.300 2.800 ;
    LAYER V1 ;
      RECT 26.800 0.000 29.800 2.800 ;
    LAYER V1 ;
      RECT 32.300 0.000 35.300 2.800 ;
    LAYER V1 ;
      RECT 37.800 0.000 40.800 2.800 ;
    LAYER V1 ;
      RECT 43.300 0.000 46.300 2.800 ;
    LAYER V1 ;
      RECT 38.600 17.100 40.000 18.500 ;
    LAYER V1 ;
      RECT 11.100 28.100 12.500 29.500 ;
    LAYER V1 ;
      RECT 8.900 4.000 20.900 53.600 ;
    LAYER V1 ;
      RECT 21.900 4.000 37.900 53.600 ;
    LAYER V1 ;
      RECT 4.800 54.800 7.800 57.800 ;
    LAYER V1 ;
      RECT 10.300 54.800 13.300 57.800 ;
    LAYER V1 ;
      RECT 15.800 54.800 18.800 57.800 ;
    LAYER V1 ;
      RECT 21.300 54.800 24.300 57.800 ;
    LAYER V1 ;
      RECT 26.800 54.800 29.800 57.800 ;
    LAYER V1 ;
      RECT 32.300 54.800 35.300 57.800 ;
    LAYER V1 ;
      RECT 37.800 54.800 40.800 57.800 ;
    LAYER V1 ;
      RECT 43.300 54.800 46.300 57.800 ;
  END
END DEL1
MACRO DEL2
  CLASS CORE ;
  ORIGIN 0 0 ;
  SIZE 73.100 BY 75.600 ;
  SYMMETRY X Y ;
  SITE TR1um_access_site ;
  PIN VDD
    DIRECTION INOUT ;
    USE POWER ;
    PORT
      LAYER M1 ;
        RECT 5.000 41.000 68.100 57.600 ;
    END
  END VDD
  PIN GND
    DIRECTION INOUT ;
    USE GROUND ;
    PORT
      LAYER M1 ;
        RECT 5.000 0.000 68.100 9.800 ;
    END
  END GND
  PIN A
    DIRECTION INPUT ;
    USE SIGNAL ;
    PORT
      LAYER M2 ;
        RECT 10.100 27.100 13.500 30.500 ;
    END
  END A
  PIN Y
    DIRECTION OUTPUT ;
    USE SIGNAL ;
    PORT
      LAYER M2 ;
        RECT 59.600 21.600 63.000 25.000 ;
    END
  END Y
  OBS
    LAYER M1 ;
      RECT 10.100 22.000 14.500 30.500 ;
    LAYER M1 ;
      RECT 9.100 6.400 18.600 51.200 ;
    LAYER M1 ;
      RECT 20.100 6.400 29.900 51.200 ;
    LAYER M1 ;
      RECT 24.100 6.400 39.900 51.200 ;
    LAYER M1 ;
      RECT 44.100 6.400 52.600 51.200 ;
    LAYER M1 ;
      RECT 48.100 6.400 57.800 51.200 ;
    LAYER M1 ;
      RECT 59.100 6.400 63.000 51.200 ;
    LAYER V1 ;
      RECT 4.800 0.000 7.800 2.800 ;
    LAYER V1 ;
      RECT 10.300 0.000 13.300 2.800 ;
    LAYER V1 ;
      RECT 15.800 0.000 18.800 2.800 ;
    LAYER V1 ;
      RECT 21.300 0.000 24.300 2.800 ;
    LAYER V1 ;
      RECT 26.800 0.000 29.800 2.800 ;
    LAYER V1 ;
      RECT 32.300 0.000 35.300 2.800 ;
    LAYER V1 ;
      RECT 37.800 0.000 40.800 2.800 ;
    LAYER V1 ;
      RECT 43.300 0.000 46.300 2.800 ;
    LAYER V1 ;
      RECT 48.800 0.000 51.800 2.800 ;
    LAYER V1 ;
      RECT 54.300 0.000 57.300 2.800 ;
    LAYER V1 ;
      RECT 59.800 0.000 62.800 2.800 ;
    LAYER V1 ;
      RECT 65.300 0.000 68.300 2.800 ;
    LAYER V1 ;
      RECT 60.600 22.600 62.000 24.000 ;
    LAYER V1 ;
      RECT 11.100 28.100 12.500 29.500 ;
    LAYER V1 ;
      RECT 8.900 4.000 22.900 53.600 ;
    LAYER V1 ;
      RECT 23.900 4.000 46.900 53.600 ;
    LAYER V1 ;
      RECT 47.900 4.000 61.900 53.600 ;
    LAYER V1 ;
      RECT 4.800 54.800 7.800 57.800 ;
    LAYER V1 ;
      RECT 10.300 54.800 13.300 57.800 ;
    LAYER V1 ;
      RECT 15.800 54.800 18.800 57.800 ;
    LAYER V1 ;
      RECT 21.300 54.800 24.300 57.800 ;
    LAYER V1 ;
      RECT 26.800 54.800 29.800 57.800 ;
    LAYER V1 ;
      RECT 32.300 54.800 35.300 57.800 ;
    LAYER V1 ;
      RECT 37.800 54.800 40.800 57.800 ;
    LAYER V1 ;
      RECT 43.300 54.800 46.300 57.800 ;
    LAYER V1 ;
      RECT 48.800 54.800 51.800 57.800 ;
    LAYER V1 ;
      RECT 54.300 54.800 57.300 57.800 ;
    LAYER V1 ;
      RECT 59.800 54.800 62.800 57.800 ;
    LAYER V1 ;
      RECT 65.300 54.800 68.300 57.800 ;
  END
END DEL2
MACRO DEL4
  CLASS CORE ;
  ORIGIN 0 0 ;
  SIZE 117.100 BY 75.600 ;
  SYMMETRY X Y ;
  SITE TR1um_access_site ;
  PIN VDD
    DIRECTION INOUT ;
    USE POWER ;
    PORT
      LAYER M1 ;
        RECT 5.000 41.000 112.100 57.600 ;
    END
  END VDD
  PIN GND
    DIRECTION INOUT ;
    USE GROUND ;
    PORT
      LAYER M1 ;
        RECT 5.000 0.000 112.100 9.800 ;
    END
  END GND
  PIN A
    DIRECTION INPUT ;
    USE SIGNAL ;
    PORT
      LAYER M2 ;
        RECT 10.100 27.100 13.500 30.500 ;
    END
  END A
  PIN Y
    DIRECTION OUTPUT ;
    USE SIGNAL ;
    PORT
      LAYER M2 ;
        RECT 103.600 21.600 107.000 25.000 ;
    END
  END Y
  OBS
    LAYER M1 ;
      RECT 10.100 22.000 14.500 30.500 ;
    LAYER M1 ;
      RECT 9.100 6.400 24.000 51.200 ;
    LAYER M1 ;
      RECT 27.100 6.400 39.900 51.200 ;
    LAYER M1 ;
      RECT 31.100 6.400 55.900 51.200 ;
    LAYER M1 ;
      RECT 61.100 6.400 73.000 51.200 ;
    LAYER M1 ;
      RECT 65.100 6.400 82.900 51.200 ;
    LAYER M1 ;
      RECT 85.100 6.400 95.900 51.200 ;
    LAYER M1 ;
      RECT 89.100 6.400 101.900 51.200 ;
    LAYER M1 ;
      RECT 102.100 6.400 107.000 51.200 ;
    LAYER V1 ;
      RECT 4.800 0.000 7.800 2.800 ;
    LAYER V1 ;
      RECT 10.300 0.000 13.300 2.800 ;
    LAYER V1 ;
      RECT 15.800 0.000 18.800 2.800 ;
    LAYER V1 ;
      RECT 21.300 0.000 24.300 2.800 ;
    LAYER V1 ;
      RECT 26.800 0.000 29.800 2.800 ;
    LAYER V1 ;
      RECT 32.300 0.000 35.300 2.800 ;
    LAYER V1 ;
      RECT 37.800 0.000 40.800 2.800 ;
    LAYER V1 ;
      RECT 43.300 0.000 46.300 2.800 ;
    LAYER V1 ;
      RECT 48.800 0.000 51.800 2.800 ;
    LAYER V1 ;
      RECT 54.300 0.000 57.300 2.800 ;
    LAYER V1 ;
      RECT 59.800 0.000 62.800 2.800 ;
    LAYER V1 ;
      RECT 65.300 0.000 68.300 2.800 ;
    LAYER V1 ;
      RECT 70.800 0.000 73.800 2.800 ;
    LAYER V1 ;
      RECT 76.300 0.000 79.300 2.800 ;
    LAYER V1 ;
      RECT 81.800 0.000 84.800 2.800 ;
    LAYER V1 ;
      RECT 87.300 0.000 90.300 2.800 ;
    LAYER V1 ;
      RECT 92.800 0.000 95.800 2.800 ;
    LAYER V1 ;
      RECT 98.300 0.000 101.300 2.800 ;
    LAYER V1 ;
      RECT 103.800 0.000 106.800 2.800 ;
    LAYER V1 ;
      RECT 109.300 0.000 112.300 2.800 ;
    LAYER V1 ;
      RECT 104.600 22.600 106.000 24.000 ;
    LAYER V1 ;
      RECT 11.100 28.100 12.500 29.500 ;
    LAYER V1 ;
      RECT 8.900 4.000 29.900 53.600 ;
    LAYER V1 ;
      RECT 30.900 4.000 63.900 53.600 ;
    LAYER V1 ;
      RECT 64.900 4.000 87.900 53.600 ;
    LAYER V1 ;
      RECT 88.900 4.000 104.900 53.600 ;
    LAYER V1 ;
      RECT 4.800 54.800 7.800 57.800 ;
    LAYER V1 ;
      RECT 10.300 54.800 13.300 57.800 ;
    LAYER V1 ;
      RECT 15.800 54.800 18.800 57.800 ;
    LAYER V1 ;
      RECT 21.300 54.800 24.300 57.800 ;
    LAYER V1 ;
      RECT 26.800 54.800 29.800 57.800 ;
    LAYER V1 ;
      RECT 32.300 54.800 35.300 57.800 ;
    LAYER V1 ;
      RECT 37.800 54.800 40.800 57.800 ;
    LAYER V1 ;
      RECT 43.300 54.800 46.300 57.800 ;
    LAYER V1 ;
      RECT 48.800 54.800 51.800 57.800 ;
    LAYER V1 ;
      RECT 54.300 54.800 57.300 57.800 ;
    LAYER V1 ;
      RECT 59.800 54.800 62.800 57.800 ;
    LAYER V1 ;
      RECT 65.300 54.800 68.300 57.800 ;
    LAYER V1 ;
      RECT 70.800 54.800 73.800 57.800 ;
    LAYER V1 ;
      RECT 76.300 54.800 79.300 57.800 ;
    LAYER V1 ;
      RECT 81.800 54.800 84.800 57.800 ;
    LAYER V1 ;
      RECT 87.300 54.800 90.300 57.800 ;
    LAYER V1 ;
      RECT 92.800 54.800 95.800 57.800 ;
    LAYER V1 ;
      RECT 98.300 54.800 101.300 57.800 ;
    LAYER V1 ;
      RECT 103.800 54.800 106.800 57.800 ;
    LAYER V1 ;
      RECT 109.300 54.800 112.300 57.800 ;
  END
END DEL4
MACRO DFFR
  CLASS CORE ;
  ORIGIN 0 0 ;
  SIZE 100.600 BY 75.600 ;
  SYMMETRY X Y ;
  SITE TR1um_access_site ;
  PIN VDD
    DIRECTION INOUT ;
    USE POWER ;
    PORT
      LAYER M1 ;
        RECT 5.000 41.000 95.600 57.600 ;
    END
  END VDD
  PIN GND
    DIRECTION INOUT ;
    USE GROUND ;
    PORT
      LAYER M1 ;
        RECT 5.000 0.000 95.600 9.800 ;
    END
  END GND
  PIN CK
    DIRECTION INPUT ;
    USE SIGNAL ;
    PORT
      LAYER M2 ;
        RECT 15.600 27.050 19.000 30.450 ;
    END
  END CK
  PIN D
    DIRECTION INPUT ;
    USE SIGNAL ;
    PORT
      LAYER M2 ;
        RECT 26.500 21.200 29.900 24.600 ;
    END
  END D
  PIN Q
    DIRECTION OUTPUT ;
    USE SIGNAL ;
    PORT
      LAYER M2 ;
        RECT 87.100 27.100 90.500 30.500 ;
    END
  END Q
  PIN QB
    DIRECTION OUTPUT ;
    USE SIGNAL ;
    PORT
      LAYER M2 ;
        RECT 81.600 27.100 85.000 30.500 ;
    END
  END QB
  PIN RST
    DIRECTION INPUT ;
    USE SIGNAL ;
    PORT
      LAYER M2 ;
        RECT 54.100 21.600 57.500 25.000 ;
    END
  END RST
  OBS
    LAYER M1 ;
      RECT 36.700 19.600 39.300 31.200 ;
    LAYER M1 ;
      RECT 13.100 14.350 19.000 34.150 ;
    LAYER M1 ;
      RECT 54.100 15.600 60.300 35.200 ;
    LAYER M1 ;
      RECT 59.100 20.200 65.100 35.200 ;
    LAYER M1 ;
      RECT 26.300 15.200 30.000 35.600 ;
    LAYER M1 ;
      RECT 9.100 6.400 11.700 51.200 ;
    LAYER M1 ;
      RECT 17.100 6.400 24.900 51.200 ;
    LAYER M1 ;
      RECT 21.100 6.400 39.300 51.200 ;
    LAYER M1 ;
      RECT 31.500 6.400 47.300 51.200 ;
    LAYER M1 ;
      RECT 40.700 6.400 57.700 51.200 ;
    LAYER M1 ;
      RECT 60.300 6.400 70.500 51.200 ;
    LAYER M1 ;
      RECT 65.500 6.400 80.600 51.200 ;
    LAYER M1 ;
      RECT 78.700 6.400 85.000 51.200 ;
    LAYER M1 ;
      RECT 86.700 6.400 90.500 51.200 ;
    LAYER V1 ;
      RECT 4.800 0.000 7.800 2.800 ;
    LAYER V1 ;
      RECT 10.300 0.000 13.300 2.800 ;
    LAYER V1 ;
      RECT 15.800 0.000 18.800 2.800 ;
    LAYER V1 ;
      RECT 21.300 0.000 24.300 2.800 ;
    LAYER V1 ;
      RECT 26.800 0.000 29.800 2.800 ;
    LAYER V1 ;
      RECT 32.300 0.000 35.300 2.800 ;
    LAYER V1 ;
      RECT 37.800 0.000 40.800 2.800 ;
    LAYER V1 ;
      RECT 43.300 0.000 46.300 2.800 ;
    LAYER V1 ;
      RECT 48.800 0.000 51.800 2.800 ;
    LAYER V1 ;
      RECT 54.300 0.000 57.300 2.800 ;
    LAYER V1 ;
      RECT 59.800 0.000 62.800 2.800 ;
    LAYER V1 ;
      RECT 65.300 0.000 68.300 2.800 ;
    LAYER V1 ;
      RECT 70.800 0.000 73.800 2.800 ;
    LAYER V1 ;
      RECT 76.300 0.000 79.300 2.800 ;
    LAYER V1 ;
      RECT 81.800 0.000 84.800 2.800 ;
    LAYER V1 ;
      RECT 87.300 0.000 90.300 2.800 ;
    LAYER V1 ;
      RECT 92.800 0.000 95.800 2.800 ;
    LAYER V1 ;
      RECT 27.500 22.200 28.900 23.600 ;
    LAYER V1 ;
      RECT 82.600 28.100 84.000 29.500 ;
    LAYER V1 ;
      RECT 88.100 28.100 89.500 29.500 ;
    LAYER V1 ;
      RECT 7.900 4.000 89.500 53.600 ;
    LAYER V1 ;
      RECT 4.800 54.800 7.800 57.800 ;
    LAYER V1 ;
      RECT 10.300 54.800 13.300 57.800 ;
    LAYER V1 ;
      RECT 15.800 54.800 18.800 57.800 ;
    LAYER V1 ;
      RECT 21.300 54.800 24.300 57.800 ;
    LAYER V1 ;
      RECT 26.800 54.800 29.800 57.800 ;
    LAYER V1 ;
      RECT 32.300 54.800 35.300 57.800 ;
    LAYER V1 ;
      RECT 37.800 54.800 40.800 57.800 ;
    LAYER V1 ;
      RECT 43.300 54.800 46.300 57.800 ;
    LAYER V1 ;
      RECT 48.800 54.800 51.800 57.800 ;
    LAYER V1 ;
      RECT 54.300 54.800 57.300 57.800 ;
    LAYER V1 ;
      RECT 59.800 54.800 62.800 57.800 ;
    LAYER V1 ;
      RECT 65.300 54.800 68.300 57.800 ;
    LAYER V1 ;
      RECT 70.800 54.800 73.800 57.800 ;
    LAYER V1 ;
      RECT 76.300 54.800 79.300 57.800 ;
    LAYER V1 ;
      RECT 81.800 54.800 84.800 57.800 ;
    LAYER V1 ;
      RECT 87.300 54.800 90.300 57.800 ;
    LAYER V1 ;
      RECT 92.800 54.800 95.800 57.800 ;
    LAYER M2 ;
      RECT 31.400 26.600 65.100 30.400 ;
  END
END DFFR
MACRO DFFS
  CLASS CORE ;
  ORIGIN 0 0 ;
  SIZE 100.600 BY 75.600 ;
  SYMMETRY X Y ;
  SITE TR1um_access_site ;
  PIN VDD
    DIRECTION INOUT ;
    USE POWER ;
    PORT
      LAYER M1 ;
        RECT 5.000 41.000 95.600 57.600 ;
    END
  END VDD
  PIN GND
    DIRECTION INOUT ;
    USE GROUND ;
    PORT
      LAYER M1 ;
        RECT 5.000 0.000 95.600 9.800 ;
    END
  END GND
  PIN CK
    DIRECTION INPUT ;
    USE SIGNAL ;
    PORT
      LAYER M2 ;
        RECT 15.600 27.100 19.000 30.500 ;
    END
  END CK
  PIN D
    DIRECTION INPUT ;
    USE SIGNAL ;
    PORT
      LAYER M2 ;
        RECT 26.500 21.600 29.900 25.000 ;
    END
  END D
  PIN Q
    DIRECTION OUTPUT ;
    USE SIGNAL ;
    PORT
      LAYER M2 ;
        RECT 87.100 27.100 90.500 30.500 ;
    END
  END Q
  PIN QB
    DIRECTION OUTPUT ;
    USE SIGNAL ;
    PORT
      LAYER M2 ;
        RECT 81.600 27.100 85.000 30.500 ;
    END
  END QB
  PIN SET
    DIRECTION INPUT ;
    USE SIGNAL ;
    PORT
      LAYER M2 ;
        RECT 76.100 16.100 79.500 19.500 ;
    END
  END SET
  OBS
    LAYER M1 ;
      RECT 76.100 16.100 79.500 22.750 ;
    LAYER M1 ;
      RECT 39.500 15.200 42.100 29.200 ;
    LAYER M1 ;
      RECT 59.900 15.200 62.500 31.600 ;
    LAYER M1 ;
      RECT 26.300 15.200 30.000 35.600 ;
    LAYER M1 ;
      RECT 49.000 17.600 51.600 35.600 ;
    LAYER M1 ;
      RECT 55.100 15.200 64.100 35.600 ;
    LAYER M1 ;
      RECT 13.100 13.600 19.000 37.200 ;
    LAYER M1 ;
      RECT 9.100 6.400 11.700 51.200 ;
    LAYER M1 ;
      RECT 17.100 6.400 24.900 51.200 ;
    LAYER M1 ;
      RECT 21.100 6.400 34.000 51.200 ;
    LAYER M1 ;
      RECT 31.500 6.400 43.200 51.200 ;
    LAYER M1 ;
      RECT 40.700 6.400 53.700 51.200 ;
    LAYER M1 ;
      RECT 58.700 6.400 70.500 51.200 ;
    LAYER M1 ;
      RECT 69.500 6.400 79.300 51.200 ;
    LAYER M1 ;
      RECT 75.500 6.400 85.000 51.200 ;
    LAYER M1 ;
      RECT 83.500 6.400 90.500 51.200 ;
    LAYER V1 ;
      RECT 4.800 0.000 7.800 2.800 ;
    LAYER V1 ;
      RECT 10.300 0.000 13.300 2.800 ;
    LAYER V1 ;
      RECT 15.800 0.000 18.800 2.800 ;
    LAYER V1 ;
      RECT 21.300 0.000 24.300 2.800 ;
    LAYER V1 ;
      RECT 26.800 0.000 29.800 2.800 ;
    LAYER V1 ;
      RECT 32.300 0.000 35.300 2.800 ;
    LAYER V1 ;
      RECT 37.800 0.000 40.800 2.800 ;
    LAYER V1 ;
      RECT 43.300 0.000 46.300 2.800 ;
    LAYER V1 ;
      RECT 48.800 0.000 51.800 2.800 ;
    LAYER V1 ;
      RECT 54.300 0.000 57.300 2.800 ;
    LAYER V1 ;
      RECT 59.800 0.000 62.800 2.800 ;
    LAYER V1 ;
      RECT 65.300 0.000 68.300 2.800 ;
    LAYER V1 ;
      RECT 70.800 0.000 73.800 2.800 ;
    LAYER V1 ;
      RECT 76.300 0.000 79.300 2.800 ;
    LAYER V1 ;
      RECT 81.800 0.000 84.800 2.800 ;
    LAYER V1 ;
      RECT 87.300 0.000 90.300 2.800 ;
    LAYER V1 ;
      RECT 92.800 0.000 95.800 2.800 ;
    LAYER V1 ;
      RECT 77.100 17.100 78.500 18.500 ;
    LAYER V1 ;
      RECT 27.500 22.600 28.900 24.000 ;
    LAYER V1 ;
      RECT 82.600 28.100 84.000 29.500 ;
    LAYER V1 ;
      RECT 88.100 28.100 89.500 29.500 ;
    LAYER V1 ;
      RECT 7.900 4.000 89.500 53.600 ;
    LAYER V1 ;
      RECT 4.800 54.800 7.800 57.800 ;
    LAYER V1 ;
      RECT 10.300 54.800 13.300 57.800 ;
    LAYER V1 ;
      RECT 15.800 54.800 18.800 57.800 ;
    LAYER V1 ;
      RECT 21.300 54.800 24.300 57.800 ;
    LAYER V1 ;
      RECT 26.800 54.800 29.800 57.800 ;
    LAYER V1 ;
      RECT 32.300 54.800 35.300 57.800 ;
    LAYER V1 ;
      RECT 37.800 54.800 40.800 57.800 ;
    LAYER V1 ;
      RECT 43.300 54.800 46.300 57.800 ;
    LAYER V1 ;
      RECT 48.800 54.800 51.800 57.800 ;
    LAYER V1 ;
      RECT 54.300 54.800 57.300 57.800 ;
    LAYER V1 ;
      RECT 59.800 54.800 62.800 57.800 ;
    LAYER V1 ;
      RECT 65.300 54.800 68.300 57.800 ;
    LAYER V1 ;
      RECT 70.800 54.800 73.800 57.800 ;
    LAYER V1 ;
      RECT 76.300 54.800 79.300 57.800 ;
    LAYER V1 ;
      RECT 81.800 54.800 84.800 57.800 ;
    LAYER V1 ;
      RECT 87.300 54.800 90.300 57.800 ;
    LAYER V1 ;
      RECT 92.800 54.800 95.800 57.800 ;
  END
END DFFS
MACRO INV_X1
  CLASS CORE ;
  ORIGIN 0 0 ;
  SIZE 29.100 BY 75.600 ;
  SYMMETRY X Y ;
  SITE TR1um_access_site ;
  PIN VDD
    DIRECTION INOUT ;
    USE POWER ;
    PORT
      LAYER M1 ;
        RECT 5.000 41.000 24.100 57.600 ;
    END
  END VDD
  PIN GND
    DIRECTION INOUT ;
    USE GROUND ;
    PORT
      LAYER M1 ;
        RECT 5.000 0.000 24.100 9.800 ;
    END
  END GND
  PIN A
    DIRECTION INPUT ;
    USE SIGNAL ;
    PORT
      LAYER M2 ;
        RECT 10.100 27.100 13.500 30.500 ;
    END
  END A
  PIN Y
    DIRECTION OUTPUT ;
    USE SIGNAL ;
    PORT
      LAYER M2 ;
        RECT 15.600 32.600 19.000 36.000 ;
    END
  END Y
  OBS
    LAYER M1 ;
      RECT 10.100 27.100 13.500 35.500 ;
    LAYER M1 ;
      RECT 13.100 6.400 19.000 51.200 ;
    LAYER V1 ;
      RECT 4.800 0.000 7.800 2.800 ;
    LAYER V1 ;
      RECT 10.300 0.000 13.300 2.800 ;
    LAYER V1 ;
      RECT 15.800 0.000 18.800 2.800 ;
    LAYER V1 ;
      RECT 21.300 0.000 24.300 2.800 ;
    LAYER V1 ;
      RECT 11.100 28.100 12.500 29.500 ;
    LAYER V1 ;
      RECT 16.600 33.600 18.000 35.000 ;
    LAYER V1 ;
      RECT 8.900 4.000 16.200 53.600 ;
    LAYER V1 ;
      RECT 4.800 54.800 7.800 57.800 ;
    LAYER V1 ;
      RECT 10.300 54.800 13.300 57.800 ;
    LAYER V1 ;
      RECT 15.800 54.800 18.800 57.800 ;
    LAYER V1 ;
      RECT 21.300 54.800 24.300 57.800 ;
  END
END INV_X1
MACRO INV_X12
  CLASS CORE ;
  ORIGIN 0 0 ;
  SIZE 73.100 BY 75.600 ;
  SYMMETRY X Y ;
  SITE TR1um_access_site ;
  PIN VDD
    DIRECTION INOUT ;
    USE POWER ;
    PORT
      LAYER M1 ;
        RECT 5.000 41.000 68.100 57.600 ;
    END
  END VDD
  PIN GND
    DIRECTION INOUT ;
    USE GROUND ;
    PORT
      LAYER M1 ;
        RECT 5.000 0.000 68.100 9.800 ;
    END
  END GND
  PIN A
    DIRECTION INPUT ;
    USE SIGNAL ;
    PORT
      LAYER M2 ;
        RECT 10.100 27.100 13.500 30.500 ;
    END
  END A
  PIN Y
    DIRECTION OUTPUT ;
    USE SIGNAL ;
    PORT
      LAYER M2 ;
        RECT 54.100 27.100 57.500 30.500 ;
    END
  END Y
  OBS
    LAYER M1 ;
      RECT 10.100 15.900 51.500 34.900 ;
    LAYER M1 ;
      RECT 13.100 6.400 57.500 51.200 ;
    LAYER V1 ;
      RECT 4.800 0.000 7.800 2.800 ;
    LAYER V1 ;
      RECT 10.300 0.000 13.300 2.800 ;
    LAYER V1 ;
      RECT 15.800 0.000 18.800 2.800 ;
    LAYER V1 ;
      RECT 21.300 0.000 24.300 2.800 ;
    LAYER V1 ;
      RECT 26.800 0.000 29.800 2.800 ;
    LAYER V1 ;
      RECT 32.300 0.000 35.300 2.800 ;
    LAYER V1 ;
      RECT 37.800 0.000 40.800 2.800 ;
    LAYER V1 ;
      RECT 43.300 0.000 46.300 2.800 ;
    LAYER V1 ;
      RECT 48.800 0.000 51.800 2.800 ;
    LAYER V1 ;
      RECT 54.300 0.000 57.300 2.800 ;
    LAYER V1 ;
      RECT 59.800 0.000 62.800 2.800 ;
    LAYER V1 ;
      RECT 65.300 0.000 68.300 2.800 ;
    LAYER V1 ;
      RECT 8.900 4.000 59.900 19.700 ;
    LAYER V1 ;
      RECT 11.100 28.100 12.500 29.500 ;
    LAYER V1 ;
      RECT 55.100 28.100 56.500 29.500 ;
    LAYER V1 ;
      RECT 8.900 31.100 59.900 53.600 ;
    LAYER V1 ;
      RECT 4.800 54.800 7.800 57.800 ;
    LAYER V1 ;
      RECT 10.300 54.800 13.300 57.800 ;
    LAYER V1 ;
      RECT 15.800 54.800 18.800 57.800 ;
    LAYER V1 ;
      RECT 21.300 54.800 24.300 57.800 ;
    LAYER V1 ;
      RECT 26.800 54.800 29.800 57.800 ;
    LAYER V1 ;
      RECT 32.300 54.800 35.300 57.800 ;
    LAYER V1 ;
      RECT 37.800 54.800 40.800 57.800 ;
    LAYER V1 ;
      RECT 43.300 54.800 46.300 57.800 ;
    LAYER V1 ;
      RECT 48.800 54.800 51.800 57.800 ;
    LAYER V1 ;
      RECT 54.300 54.800 57.300 57.800 ;
    LAYER V1 ;
      RECT 59.800 54.800 62.800 57.800 ;
    LAYER V1 ;
      RECT 65.300 54.800 68.300 57.800 ;
  END
END INV_X12
MACRO INV_X16
  CLASS CORE ;
  ORIGIN 0 0 ;
  SIZE 89.600 BY 75.600 ;
  SYMMETRY X Y ;
  SITE TR1um_access_site ;
  PIN VDD
    DIRECTION INOUT ;
    USE POWER ;
    PORT
      LAYER M1 ;
        RECT 5.000 41.000 84.600 57.600 ;
    END
  END VDD
  PIN GND
    DIRECTION INOUT ;
    USE GROUND ;
    PORT
      LAYER M1 ;
        RECT 5.000 0.000 84.600 9.800 ;
    END
  END GND
  PIN A
    DIRECTION INPUT ;
    USE SIGNAL ;
    PORT
      LAYER M2 ;
        RECT 10.100 27.100 13.500 30.500 ;
    END
  END A
  PIN Y
    DIRECTION OUTPUT ;
    USE SIGNAL ;
    PORT
      LAYER M2 ;
        RECT 70.600 27.100 74.000 30.500 ;
    END
  END Y
  OBS
    LAYER M1 ;
      RECT 10.100 15.900 67.500 34.900 ;
    LAYER M1 ;
      RECT 13.100 6.400 74.000 51.200 ;
    LAYER V1 ;
      RECT 4.800 0.000 7.800 2.800 ;
    LAYER V1 ;
      RECT 10.300 0.000 13.300 2.800 ;
    LAYER V1 ;
      RECT 15.800 0.000 18.800 2.800 ;
    LAYER V1 ;
      RECT 21.300 0.000 24.300 2.800 ;
    LAYER V1 ;
      RECT 26.800 0.000 29.800 2.800 ;
    LAYER V1 ;
      RECT 32.300 0.000 35.300 2.800 ;
    LAYER V1 ;
      RECT 37.800 0.000 40.800 2.800 ;
    LAYER V1 ;
      RECT 43.300 0.000 46.300 2.800 ;
    LAYER V1 ;
      RECT 48.800 0.000 51.800 2.800 ;
    LAYER V1 ;
      RECT 54.300 0.000 57.300 2.800 ;
    LAYER V1 ;
      RECT 59.800 0.000 62.800 2.800 ;
    LAYER V1 ;
      RECT 65.300 0.000 68.300 2.800 ;
    LAYER V1 ;
      RECT 70.800 0.000 73.800 2.800 ;
    LAYER V1 ;
      RECT 76.300 0.000 79.300 2.800 ;
    LAYER V1 ;
      RECT 81.800 0.000 84.800 2.800 ;
    LAYER V1 ;
      RECT 8.900 4.000 75.900 19.700 ;
    LAYER V1 ;
      RECT 11.100 28.100 12.500 29.500 ;
    LAYER V1 ;
      RECT 71.600 28.100 73.000 29.500 ;
    LAYER V1 ;
      RECT 8.900 31.100 75.900 53.600 ;
    LAYER V1 ;
      RECT 4.800 54.800 7.800 57.800 ;
    LAYER V1 ;
      RECT 10.300 54.800 13.300 57.800 ;
    LAYER V1 ;
      RECT 15.800 54.800 18.800 57.800 ;
    LAYER V1 ;
      RECT 21.300 54.800 24.300 57.800 ;
    LAYER V1 ;
      RECT 26.800 54.800 29.800 57.800 ;
    LAYER V1 ;
      RECT 32.300 54.800 35.300 57.800 ;
    LAYER V1 ;
      RECT 37.800 54.800 40.800 57.800 ;
    LAYER V1 ;
      RECT 43.300 54.800 46.300 57.800 ;
    LAYER V1 ;
      RECT 48.800 54.800 51.800 57.800 ;
    LAYER V1 ;
      RECT 54.300 54.800 57.300 57.800 ;
    LAYER V1 ;
      RECT 59.800 54.800 62.800 57.800 ;
    LAYER V1 ;
      RECT 65.300 54.800 68.300 57.800 ;
    LAYER V1 ;
      RECT 70.800 54.800 73.800 57.800 ;
    LAYER V1 ;
      RECT 76.300 54.800 79.300 57.800 ;
    LAYER V1 ;
      RECT 81.800 54.800 84.800 57.800 ;
  END
END INV_X16
MACRO INV_X2
  CLASS CORE ;
  ORIGIN 0 0 ;
  SIZE 29.100 BY 75.600 ;
  SYMMETRY X Y ;
  SITE TR1um_access_site ;
  PIN VDD
    DIRECTION INOUT ;
    USE POWER ;
    PORT
      LAYER M1 ;
        RECT 5.000 41.000 24.100 57.600 ;
    END
  END VDD
  PIN GND
    DIRECTION INOUT ;
    USE GROUND ;
    PORT
      LAYER M1 ;
        RECT 5.000 0.000 24.100 9.800 ;
    END
  END GND
  PIN A
    DIRECTION INPUT ;
    USE SIGNAL ;
    PORT
      LAYER M2 ;
        RECT 10.100 27.100 13.500 30.500 ;
    END
  END A
  PIN Y
    DIRECTION OUTPUT ;
    USE SIGNAL ;
    PORT
      LAYER M2 ;
        RECT 15.600 32.600 19.000 36.000 ;
    END
  END Y
  OBS
    LAYER M1 ;
      RECT 10.100 27.100 13.500 35.500 ;
    LAYER M1 ;
      RECT 13.100 6.400 19.000 51.200 ;
    LAYER V1 ;
      RECT 4.800 0.000 7.800 2.800 ;
    LAYER V1 ;
      RECT 10.300 0.000 13.300 2.800 ;
    LAYER V1 ;
      RECT 15.800 0.000 18.800 2.800 ;
    LAYER V1 ;
      RECT 21.300 0.000 24.300 2.800 ;
    LAYER V1 ;
      RECT 11.100 28.100 12.500 29.500 ;
    LAYER V1 ;
      RECT 16.600 33.600 18.000 35.000 ;
    LAYER V1 ;
      RECT 8.900 4.000 19.900 53.600 ;
    LAYER V1 ;
      RECT 4.800 54.800 7.800 57.800 ;
    LAYER V1 ;
      RECT 10.300 54.800 13.300 57.800 ;
    LAYER V1 ;
      RECT 15.800 54.800 18.800 57.800 ;
    LAYER V1 ;
      RECT 21.300 54.800 24.300 57.800 ;
  END
END INV_X2
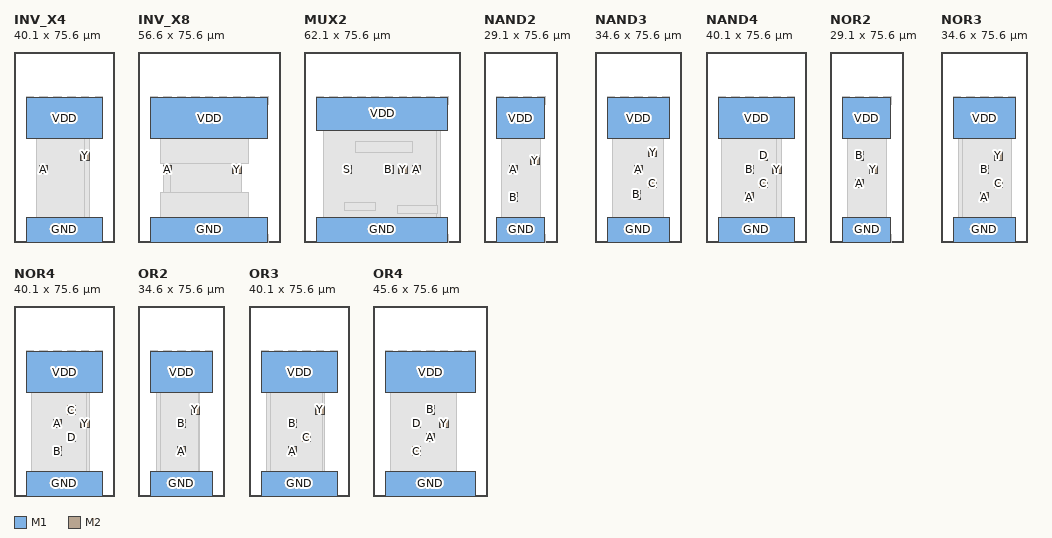
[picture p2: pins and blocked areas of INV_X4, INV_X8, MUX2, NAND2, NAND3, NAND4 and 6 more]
MACRO INV_X4
  CLASS CORE ;
  ORIGIN 0 0 ;
  SIZE 40.100 BY 75.600 ;
  SYMMETRY X Y ;
  SITE TR1um_access_site ;
  PIN VDD
    DIRECTION INOUT ;
    USE POWER ;
    PORT
      LAYER M1 ;
        RECT 5.000 41.000 35.100 57.600 ;
    END
  END VDD
  PIN GND
    DIRECTION INOUT ;
    USE GROUND ;
    PORT
      LAYER M1 ;
        RECT 5.000 0.000 35.100 9.800 ;
    END
  END GND
  PIN A
    DIRECTION INPUT ;
    USE SIGNAL ;
    PORT
      LAYER M2 ;
        RECT 10.100 27.100 13.500 30.500 ;
    END
  END A
  PIN Y
    DIRECTION OUTPUT ;
    USE SIGNAL ;
    PORT
      LAYER M2 ;
        RECT 26.600 32.600 30.000 36.000 ;
    END
  END Y
  OBS
    LAYER M1 ;
      RECT 10.100 27.100 18.400 30.500 ;
    LAYER M1 ;
      RECT 13.100 6.400 30.000 51.200 ;
    LAYER V1 ;
      RECT 4.800 0.000 7.800 2.800 ;
    LAYER V1 ;
      RECT 10.300 0.000 13.300 2.800 ;
    LAYER V1 ;
      RECT 15.800 0.000 18.800 2.800 ;
    LAYER V1 ;
      RECT 21.300 0.000 24.300 2.800 ;
    LAYER V1 ;
      RECT 26.800 0.000 29.800 2.800 ;
    LAYER V1 ;
      RECT 32.300 0.000 35.300 2.800 ;
    LAYER V1 ;
      RECT 11.100 28.100 12.500 29.500 ;
    LAYER V1 ;
      RECT 27.600 33.600 29.000 35.000 ;
    LAYER V1 ;
      RECT 8.900 4.000 27.900 53.600 ;
    LAYER V1 ;
      RECT 4.800 54.800 7.800 57.800 ;
    LAYER V1 ;
      RECT 10.300 54.800 13.300 57.800 ;
    LAYER V1 ;
      RECT 15.800 54.800 18.800 57.800 ;
    LAYER V1 ;
      RECT 21.300 54.800 24.300 57.800 ;
    LAYER V1 ;
      RECT 26.800 54.800 29.800 57.800 ;
    LAYER V1 ;
      RECT 32.300 54.800 35.300 57.800 ;
  END
END INV_X4
MACRO INV_X8
  CLASS CORE ;
  ORIGIN 0 0 ;
  SIZE 56.600 BY 75.600 ;
  SYMMETRY X Y ;
  SITE TR1um_access_site ;
  PIN VDD
    DIRECTION INOUT ;
    USE POWER ;
    PORT
      LAYER M1 ;
        RECT 5.000 41.000 51.600 57.600 ;
    END
  END VDD
  PIN GND
    DIRECTION INOUT ;
    USE GROUND ;
    PORT
      LAYER M1 ;
        RECT 5.000 0.000 51.600 9.800 ;
    END
  END GND
  PIN A
    DIRECTION INPUT ;
    USE SIGNAL ;
    PORT
      LAYER M2 ;
        RECT 10.100 27.100 13.500 30.500 ;
    END
  END A
  PIN Y
    DIRECTION OUTPUT ;
    USE SIGNAL ;
    PORT
      LAYER M2 ;
        RECT 37.600 27.100 41.000 30.500 ;
    END
  END Y
  OBS
    LAYER M1 ;
      RECT 10.100 15.900 34.500 34.900 ;
    LAYER M1 ;
      RECT 13.100 6.400 41.000 51.200 ;
    LAYER V1 ;
      RECT 4.800 0.000 7.800 2.800 ;
    LAYER V1 ;
      RECT 10.300 0.000 13.300 2.800 ;
    LAYER V1 ;
      RECT 15.800 0.000 18.800 2.800 ;
    LAYER V1 ;
      RECT 21.300 0.000 24.300 2.800 ;
    LAYER V1 ;
      RECT 26.800 0.000 29.800 2.800 ;
    LAYER V1 ;
      RECT 32.300 0.000 35.300 2.800 ;
    LAYER V1 ;
      RECT 37.800 0.000 40.800 2.800 ;
    LAYER V1 ;
      RECT 43.300 0.000 46.300 2.800 ;
    LAYER V1 ;
      RECT 48.800 0.000 51.800 2.800 ;
    LAYER V1 ;
      RECT 8.900 4.000 43.900 19.700 ;
    LAYER V1 ;
      RECT 11.100 28.100 12.500 29.500 ;
    LAYER V1 ;
      RECT 38.600 28.100 40.000 29.500 ;
    LAYER V1 ;
      RECT 8.900 31.100 43.900 53.600 ;
    LAYER V1 ;
      RECT 4.800 54.800 7.800 57.800 ;
    LAYER V1 ;
      RECT 10.300 54.800 13.300 57.800 ;
    LAYER V1 ;
      RECT 15.800 54.800 18.800 57.800 ;
    LAYER V1 ;
      RECT 21.300 54.800 24.300 57.800 ;
    LAYER V1 ;
      RECT 26.800 54.800 29.800 57.800 ;
    LAYER V1 ;
      RECT 32.300 54.800 35.300 57.800 ;
    LAYER V1 ;
      RECT 37.800 54.800 40.800 57.800 ;
    LAYER V1 ;
      RECT 43.300 54.800 46.300 57.800 ;
    LAYER V1 ;
      RECT 48.800 54.800 51.800 57.800 ;
  END
END INV_X8
MACRO MUX2
  CLASS CORE ;
  ORIGIN 0 0 ;
  SIZE 62.100 BY 75.600 ;
  SYMMETRY X Y ;
  SITE TR1um_access_site ;
  PIN VDD
    DIRECTION INOUT ;
    USE POWER ;
    PORT
      LAYER M1 ;
        RECT 5.000 44.400 57.100 57.600 ;
    END
  END VDD
  PIN GND
    DIRECTION INOUT ;
    USE GROUND ;
    PORT
      LAYER M1 ;
        RECT 5.000 0.000 57.100 9.800 ;
    END
  END GND
  PIN A
    DIRECTION INPUT ;
    USE SIGNAL ;
    PORT
      LAYER M2 ;
        RECT 43.000 27.100 46.400 30.500 ;
    END
  END A
  PIN B
    DIRECTION INPUT ;
    USE SIGNAL ;
    PORT
      LAYER M2 ;
        RECT 32.100 27.100 35.500 30.500 ;
    END
  END B
  PIN S
    DIRECTION OUTPUT ;
    USE SIGNAL ;
    PORT
      LAYER M2 ;
        RECT 15.600 27.100 19.000 30.500 ;
    END
  END S
  PIN Y
    DIRECTION OUTPUT ;
    USE SIGNAL ;
    PORT
      LAYER M2 ;
        RECT 37.600 27.100 41.000 30.500 ;
    END
  END Y
  OBS
    LAYER M1 ;
      RECT 37.100 6.400 40.500 14.600 ;
    LAYER M1 ;
      RECT 16.300 6.400 19.700 15.800 ;
    LAYER M1 ;
      RECT 43.000 20.000 46.500 35.000 ;
    LAYER M1 ;
      RECT 29.100 17.200 35.500 42.300 ;
    LAYER M1 ;
      RECT 13.100 17.200 19.000 43.000 ;
    LAYER M1 ;
      RECT 9.100 6.400 11.700 51.200 ;
    LAYER M1 ;
      RECT 17.100 6.400 23.700 51.200 ;
    LAYER M1 ;
      RECT 21.100 6.400 28.500 51.200 ;
    LAYER M1 ;
      RECT 33.100 6.400 41.000 51.200 ;
    LAYER M1 ;
      RECT 37.100 6.400 50.500 51.200 ;
    LAYER M1 ;
      RECT 45.100 6.400 54.500 51.200 ;
    LAYER V1 ;
      RECT 4.800 0.000 7.800 2.800 ;
    LAYER V1 ;
      RECT 10.300 0.000 13.300 2.800 ;
    LAYER V1 ;
      RECT 15.800 0.000 18.800 2.800 ;
    LAYER V1 ;
      RECT 21.300 0.000 24.300 2.800 ;
    LAYER V1 ;
      RECT 26.800 0.000 29.800 2.800 ;
    LAYER V1 ;
      RECT 32.300 0.000 35.300 2.800 ;
    LAYER V1 ;
      RECT 37.800 0.000 40.800 2.800 ;
    LAYER V1 ;
      RECT 43.300 0.000 46.300 2.800 ;
    LAYER V1 ;
      RECT 48.800 0.000 51.800 2.800 ;
    LAYER V1 ;
      RECT 54.300 0.000 57.300 2.800 ;
    LAYER V1 ;
      RECT 16.600 28.100 18.000 29.500 ;
    LAYER V1 ;
      RECT 33.100 28.100 34.500 29.500 ;
    LAYER V1 ;
      RECT 38.600 28.100 40.000 29.500 ;
    LAYER V1 ;
      RECT 44.000 28.100 45.400 29.500 ;
    LAYER V1 ;
      RECT 7.900 35.200 42.300 53.600 ;
    LAYER V1 ;
      RECT 7.900 4.000 52.700 53.600 ;
    LAYER V1 ;
      RECT 4.800 54.800 7.800 57.800 ;
    LAYER V1 ;
      RECT 10.300 54.800 13.300 57.800 ;
    LAYER V1 ;
      RECT 15.800 54.800 18.800 57.800 ;
    LAYER V1 ;
      RECT 21.300 54.800 24.300 57.800 ;
    LAYER V1 ;
      RECT 26.800 54.800 29.800 57.800 ;
    LAYER V1 ;
      RECT 32.300 54.800 35.300 57.800 ;
    LAYER V1 ;
      RECT 37.800 54.800 40.800 57.800 ;
    LAYER V1 ;
      RECT 43.300 54.800 46.300 57.800 ;
    LAYER V1 ;
      RECT 48.800 54.800 51.800 57.800 ;
    LAYER V1 ;
      RECT 54.300 54.800 57.300 57.800 ;
    LAYER M2 ;
      RECT 37.100 11.200 53.300 14.600 ;
    LAYER M2 ;
      RECT 16.300 12.400 28.500 15.800 ;
    LAYER M2 ;
      RECT 20.300 35.600 43.300 39.800 ;
  END
END MUX2
MACRO NAND2
  CLASS CORE ;
  ORIGIN 0 0 ;
  SIZE 29.100 BY 75.600 ;
  SYMMETRY X Y ;
  SITE TR1um_access_site ;
  PIN VDD
    DIRECTION INOUT ;
    USE POWER ;
    PORT
      LAYER M1 ;
        RECT 5.000 41.000 24.100 57.600 ;
    END
  END VDD
  PIN GND
    DIRECTION INOUT ;
    USE GROUND ;
    PORT
      LAYER M1 ;
        RECT 5.000 0.000 24.100 9.800 ;
    END
  END GND
  PIN A
    DIRECTION INPUT ;
    USE SIGNAL ;
    PORT
      LAYER M2 ;
        RECT 10.100 27.100 13.500 30.500 ;
    END
  END A
  PIN B
    DIRECTION INPUT ;
    USE SIGNAL ;
    PORT
      LAYER M2 ;
        RECT 10.100 16.100 13.500 19.500 ;
    END
  END B
  PIN Y
    DIRECTION OUTPUT ;
    USE SIGNAL ;
    PORT
      LAYER M2 ;
        RECT 18.700 30.900 22.100 34.300 ;
    END
  END Y
  OBS
    LAYER M1 ;
      RECT 13.100 6.400 15.700 9.800 ;
    LAYER M1 ;
      RECT 10.100 15.300 18.100 19.500 ;
    LAYER M1 ;
      RECT 10.100 27.100 13.500 34.800 ;
    LAYER M1 ;
      RECT 13.100 6.400 22.100 51.200 ;
    LAYER V1 ;
      RECT 4.800 0.000 7.800 2.800 ;
    LAYER V1 ;
      RECT 10.300 0.000 13.300 2.800 ;
    LAYER V1 ;
      RECT 15.800 0.000 18.800 2.800 ;
    LAYER V1 ;
      RECT 21.300 0.000 24.300 2.800 ;
    LAYER V1 ;
      RECT 11.100 17.100 12.500 18.500 ;
    LAYER V1 ;
      RECT 11.100 28.100 12.500 29.500 ;
    LAYER V1 ;
      RECT 19.700 31.900 21.100 33.300 ;
    LAYER V1 ;
      RECT 6.900 4.000 22.500 53.600 ;
    LAYER V1 ;
      RECT 4.800 54.800 7.800 57.800 ;
    LAYER V1 ;
      RECT 10.300 54.800 13.300 57.800 ;
    LAYER V1 ;
      RECT 15.800 54.800 18.800 57.800 ;
    LAYER V1 ;
      RECT 21.300 54.800 24.300 57.800 ;
  END
END NAND2
MACRO NAND3
  CLASS CORE ;
  ORIGIN 0 0 ;
  SIZE 34.600 BY 75.600 ;
  SYMMETRY X Y ;
  SITE TR1um_access_site ;
  PIN VDD
    DIRECTION INOUT ;
    USE POWER ;
    PORT
      LAYER M1 ;
        RECT 5.000 41.000 29.600 57.600 ;
    END
  END VDD
  PIN GND
    DIRECTION INOUT ;
    USE GROUND ;
    PORT
      LAYER M1 ;
        RECT 5.000 0.000 29.600 9.800 ;
    END
  END GND
  PIN A
    DIRECTION INPUT ;
    USE SIGNAL ;
    PORT
      LAYER M2 ;
        RECT 15.600 27.100 19.000 30.500 ;
    END
  END A
  PIN B
    DIRECTION INPUT ;
    USE SIGNAL ;
    PORT
      LAYER M2 ;
        RECT 14.800 17.100 18.200 20.500 ;
    END
  END B
  PIN C
    DIRECTION INPUT ;
    USE SIGNAL ;
    PORT
      LAYER M2 ;
        RECT 21.100 21.550 24.500 24.950 ;
    END
  END C
  PIN Y
    DIRECTION OUTPUT ;
    USE SIGNAL ;
    PORT
      LAYER M2 ;
        RECT 21.200 33.900 24.600 37.300 ;
    END
  END Y
  OBS
    LAYER M1 ;
      RECT 13.100 6.400 15.700 9.800 ;
    LAYER M1 ;
      RECT 17.100 6.400 19.700 9.800 ;
    LAYER M1 ;
      RECT 12.000 14.600 19.000 20.500 ;
    LAYER M1 ;
      RECT 21.100 16.950 26.000 25.000 ;
    LAYER M1 ;
      RECT 10.700 27.100 19.000 35.800 ;
    LAYER M1 ;
      RECT 7.300 6.400 24.600 51.200 ;
    LAYER V1 ;
      RECT 4.800 0.000 7.800 2.800 ;
    LAYER V1 ;
      RECT 10.300 0.000 13.300 2.800 ;
    LAYER V1 ;
      RECT 15.800 0.000 18.800 2.800 ;
    LAYER V1 ;
      RECT 21.300 0.000 24.300 2.800 ;
    LAYER V1 ;
      RECT 26.800 0.000 29.800 2.800 ;
    LAYER V1 ;
      RECT 22.100 22.550 23.500 23.950 ;
    LAYER V1 ;
      RECT 16.600 28.100 18.000 29.500 ;
    LAYER V1 ;
      RECT 22.200 34.900 23.600 36.300 ;
    LAYER V1 ;
      RECT 7.100 4.000 27.200 53.600 ;
    LAYER V1 ;
      RECT 4.800 54.800 7.800 57.800 ;
    LAYER V1 ;
      RECT 10.300 54.800 13.300 57.800 ;
    LAYER V1 ;
      RECT 15.800 54.800 18.800 57.800 ;
    LAYER V1 ;
      RECT 21.300 54.800 24.300 57.800 ;
    LAYER V1 ;
      RECT 26.800 54.800 29.800 57.800 ;
  END
END NAND3
MACRO NAND4
  CLASS CORE ;
  ORIGIN 0 0 ;
  SIZE 40.100 BY 75.600 ;
  SYMMETRY X Y ;
  SITE TR1um_access_site ;
  PIN VDD
    DIRECTION INOUT ;
    USE POWER ;
    PORT
      LAYER M1 ;
        RECT 5.000 41.000 35.100 57.600 ;
    END
  END VDD
  PIN GND
    DIRECTION INOUT ;
    USE GROUND ;
    PORT
      LAYER M1 ;
        RECT 5.000 0.000 35.100 9.800 ;
    END
  END GND
  PIN A
    DIRECTION INPUT ;
    USE SIGNAL ;
    PORT
      LAYER M2 ;
        RECT 15.600 16.100 19.000 19.500 ;
    END
  END A
  PIN B
    DIRECTION INPUT ;
    USE SIGNAL ;
    PORT
      LAYER M2 ;
        RECT 15.600 27.100 19.000 30.500 ;
    END
  END B
  PIN C
    DIRECTION INPUT ;
    USE SIGNAL ;
    PORT
      LAYER M2 ;
        RECT 21.100 21.600 24.500 25.000 ;
    END
  END C
  PIN D
    DIRECTION INPUT ;
    USE SIGNAL ;
    PORT
      LAYER M2 ;
        RECT 21.100 32.600 24.500 36.000 ;
    END
  END D
  PIN Y
    DIRECTION OUTPUT ;
    USE SIGNAL ;
    PORT
      LAYER M2 ;
        RECT 26.600 27.100 30.000 30.500 ;
    END
  END Y
  OBS
    LAYER M1 ;
      RECT 13.100 6.400 15.700 9.800 ;
    LAYER M1 ;
      RECT 17.100 6.400 19.700 9.800 ;
    LAYER M1 ;
      RECT 21.100 6.400 23.700 9.800 ;
    LAYER M1 ;
      RECT 7.200 11.700 19.000 19.500 ;
    LAYER M1 ;
      RECT 17.900 21.600 24.500 25.000 ;
    LAYER M1 ;
      RECT 10.500 23.900 19.000 30.500 ;
    LAYER M1 ;
      RECT 21.100 28.400 24.800 36.000 ;
    LAYER M1 ;
      RECT 13.100 6.400 30.000 51.200 ;
    LAYER V1 ;
      RECT 4.800 0.000 7.800 2.800 ;
    LAYER V1 ;
      RECT 10.300 0.000 13.300 2.800 ;
    LAYER V1 ;
      RECT 15.800 0.000 18.800 2.800 ;
    LAYER V1 ;
      RECT 21.300 0.000 24.300 2.800 ;
    LAYER V1 ;
      RECT 26.800 0.000 29.800 2.800 ;
    LAYER V1 ;
      RECT 32.300 0.000 35.300 2.800 ;
    LAYER V1 ;
      RECT 16.600 17.100 18.000 18.500 ;
    LAYER V1 ;
      RECT 22.100 22.600 23.500 24.000 ;
    LAYER V1 ;
      RECT 16.600 28.100 18.000 29.500 ;
    LAYER V1 ;
      RECT 27.600 28.100 29.000 29.500 ;
    LAYER V1 ;
      RECT 22.100 33.600 23.500 35.000 ;
    LAYER V1 ;
      RECT 6.000 4.000 27.900 53.600 ;
    LAYER V1 ;
      RECT 4.800 54.800 7.800 57.800 ;
    LAYER V1 ;
      RECT 10.300 54.800 13.300 57.800 ;
    LAYER V1 ;
      RECT 15.800 54.800 18.800 57.800 ;
    LAYER V1 ;
      RECT 21.300 54.800 24.300 57.800 ;
    LAYER V1 ;
      RECT 26.800 54.800 29.800 57.800 ;
    LAYER V1 ;
      RECT 32.300 54.800 35.300 57.800 ;
  END
END NAND4
MACRO NOR2
  CLASS CORE ;
  ORIGIN 0 0 ;
  SIZE 29.100 BY 75.600 ;
  SYMMETRY X Y ;
  SITE TR1um_access_site ;
  PIN VDD
    DIRECTION INOUT ;
    USE POWER ;
    PORT
      LAYER M1 ;
        RECT 5.000 41.000 24.100 57.600 ;
    END
  END VDD
  PIN GND
    DIRECTION INOUT ;
    USE GROUND ;
    PORT
      LAYER M1 ;
        RECT 5.000 0.000 24.100 9.800 ;
    END
  END GND
  PIN A
    DIRECTION INPUT ;
    USE SIGNAL ;
    PORT
      LAYER M2 ;
        RECT 10.100 21.600 13.500 25.000 ;
    END
  END A
  PIN B
    DIRECTION INPUT ;
    USE SIGNAL ;
    PORT
      LAYER M2 ;
        RECT 10.100 32.600 13.500 36.000 ;
    END
  END B
  PIN Y
    DIRECTION OUTPUT ;
    USE SIGNAL ;
    PORT
      LAYER M2 ;
        RECT 15.600 27.100 19.000 30.500 ;
    END
  END Y
  OBS
    LAYER M1 ;
      RECT 10.100 16.000 13.500 25.000 ;
    LAYER M1 ;
      RECT 10.100 32.600 18.100 36.000 ;
    LAYER M1 ;
      RECT 13.100 41.000 15.700 51.200 ;
    LAYER M1 ;
      RECT 13.100 6.400 21.500 51.200 ;
    LAYER V1 ;
      RECT 4.800 0.000 7.800 2.800 ;
    LAYER V1 ;
      RECT 10.300 0.000 13.300 2.800 ;
    LAYER V1 ;
      RECT 15.800 0.000 18.800 2.800 ;
    LAYER V1 ;
      RECT 21.300 0.000 24.300 2.800 ;
    LAYER V1 ;
      RECT 11.100 22.600 12.500 24.000 ;
    LAYER V1 ;
      RECT 16.600 28.100 18.000 29.500 ;
    LAYER V1 ;
      RECT 11.100 33.600 12.500 35.000 ;
    LAYER V1 ;
      RECT 6.900 4.000 22.500 53.600 ;
    LAYER V1 ;
      RECT 4.800 54.800 7.800 57.800 ;
    LAYER V1 ;
      RECT 10.300 54.800 13.300 57.800 ;
    LAYER V1 ;
      RECT 15.800 54.800 18.800 57.800 ;
    LAYER V1 ;
      RECT 21.300 54.800 24.300 57.800 ;
  END
END NOR2
MACRO NOR3
  CLASS CORE ;
  ORIGIN 0 0 ;
  SIZE 34.600 BY 75.600 ;
  SYMMETRY X Y ;
  SITE TR1um_access_site ;
  PIN VDD
    DIRECTION INOUT ;
    USE POWER ;
    PORT
      LAYER M1 ;
        RECT 5.000 41.000 29.600 57.600 ;
    END
  END VDD
  PIN GND
    DIRECTION INOUT ;
    USE GROUND ;
    PORT
      LAYER M1 ;
        RECT 5.000 0.000 29.600 9.800 ;
    END
  END GND
  PIN A
    DIRECTION INPUT ;
    USE SIGNAL ;
    PORT
      LAYER M2 ;
        RECT 15.600 16.100 19.000 19.500 ;
    END
  END A
  PIN B
    DIRECTION INPUT ;
    USE SIGNAL ;
    PORT
      LAYER M2 ;
        RECT 15.600 27.100 19.000 30.500 ;
    END
  END B
  PIN C
    DIRECTION INPUT ;
    USE SIGNAL ;
    PORT
      LAYER M2 ;
        RECT 21.100 21.600 24.500 25.000 ;
    END
  END C
  PIN Y
    DIRECTION OUTPUT ;
    USE SIGNAL ;
    PORT
      LAYER M2 ;
        RECT 21.100 32.600 24.500 36.000 ;
    END
  END Y
  OBS
    LAYER M1 ;
      RECT 12.600 16.100 19.000 23.900 ;
    LAYER M1 ;
      RECT 21.100 16.500 24.500 25.000 ;
    LAYER M1 ;
      RECT 10.400 27.100 19.000 35.700 ;
    LAYER M1 ;
      RECT 13.100 41.000 15.700 51.200 ;
    LAYER M1 ;
      RECT 17.100 41.000 19.700 51.200 ;
    LAYER M1 ;
      RECT 7.100 6.400 24.500 51.200 ;
    LAYER V1 ;
      RECT 4.800 0.000 7.800 2.800 ;
    LAYER V1 ;
      RECT 10.300 0.000 13.300 2.800 ;
    LAYER V1 ;
      RECT 15.800 0.000 18.800 2.800 ;
    LAYER V1 ;
      RECT 21.300 0.000 24.300 2.800 ;
    LAYER V1 ;
      RECT 26.800 0.000 29.800 2.800 ;
    LAYER V1 ;
      RECT 16.600 17.100 18.000 18.500 ;
    LAYER V1 ;
      RECT 22.100 22.600 23.500 24.000 ;
    LAYER V1 ;
      RECT 16.600 28.100 18.000 29.500 ;
    LAYER V1 ;
      RECT 22.100 33.600 23.500 35.000 ;
    LAYER V1 ;
      RECT 8.700 4.000 28.200 53.600 ;
    LAYER V1 ;
      RECT 4.800 54.800 7.800 57.800 ;
    LAYER V1 ;
      RECT 10.300 54.800 13.300 57.800 ;
    LAYER V1 ;
      RECT 15.800 54.800 18.800 57.800 ;
    LAYER V1 ;
      RECT 21.300 54.800 24.300 57.800 ;
    LAYER V1 ;
      RECT 26.800 54.800 29.800 57.800 ;
  END
END NOR3
MACRO NOR4
  CLASS CORE ;
  ORIGIN 0 0 ;
  SIZE 40.100 BY 75.600 ;
  SYMMETRY X Y ;
  SITE TR1um_access_site ;
  PIN VDD
    DIRECTION INOUT ;
    USE POWER ;
    PORT
      LAYER M1 ;
        RECT 5.000 41.000 35.100 57.600 ;
    END
  END VDD
  PIN GND
    DIRECTION INOUT ;
    USE GROUND ;
    PORT
      LAYER M1 ;
        RECT 5.000 0.000 35.100 9.800 ;
    END
  END GND
  PIN A
    DIRECTION INPUT ;
    USE SIGNAL ;
    PORT
      LAYER M2 ;
        RECT 15.600 27.100 19.000 30.500 ;
    END
  END A
  PIN B
    DIRECTION INPUT ;
    USE SIGNAL ;
    PORT
      LAYER M2 ;
        RECT 15.600 16.100 19.000 19.500 ;
    END
  END B
  PIN C
    DIRECTION INPUT ;
    USE SIGNAL ;
    PORT
      LAYER M2 ;
        RECT 21.100 32.500 24.500 35.900 ;
    END
  END C
  PIN D
    DIRECTION INPUT ;
    USE SIGNAL ;
    PORT
      LAYER M2 ;
        RECT 21.100 21.600 24.500 25.000 ;
    END
  END D
  PIN Y
    DIRECTION OUTPUT ;
    USE SIGNAL ;
    PORT
      LAYER M2 ;
        RECT 26.600 27.100 30.000 30.500 ;
    END
  END Y
  OBS
    LAYER M1 ;
      RECT 12.000 14.600 19.000 19.500 ;
    LAYER M1 ;
      RECT 21.100 21.600 27.600 25.000 ;
    LAYER M1 ;
      RECT 10.700 27.100 19.000 35.800 ;
    LAYER M1 ;
      RECT 18.100 32.500 24.500 36.000 ;
    LAYER M1 ;
      RECT 13.100 41.000 15.700 51.200 ;
    LAYER M1 ;
      RECT 17.100 41.000 19.700 51.200 ;
    LAYER M1 ;
      RECT 21.100 41.000 23.700 51.200 ;
    LAYER M1 ;
      RECT 7.300 6.400 30.000 51.200 ;
    LAYER V1 ;
      RECT 4.800 0.000 7.800 2.800 ;
    LAYER V1 ;
      RECT 10.300 0.000 13.300 2.800 ;
    LAYER V1 ;
      RECT 15.800 0.000 18.800 2.800 ;
    LAYER V1 ;
      RECT 21.300 0.000 24.300 2.800 ;
    LAYER V1 ;
      RECT 26.800 0.000 29.800 2.800 ;
    LAYER V1 ;
      RECT 32.300 0.000 35.300 2.800 ;
    LAYER V1 ;
      RECT 16.600 17.100 18.000 18.500 ;
    LAYER V1 ;
      RECT 22.100 22.600 23.500 24.000 ;
    LAYER V1 ;
      RECT 16.600 28.100 18.000 29.500 ;
    LAYER V1 ;
      RECT 27.600 28.100 29.000 29.500 ;
    LAYER V1 ;
      RECT 22.100 33.500 23.500 34.900 ;
    LAYER V1 ;
      RECT 7.100 4.000 28.800 53.600 ;
    LAYER V1 ;
      RECT 4.800 54.800 7.800 57.800 ;
    LAYER V1 ;
      RECT 10.300 54.800 13.300 57.800 ;
    LAYER V1 ;
      RECT 15.800 54.800 18.800 57.800 ;
    LAYER V1 ;
      RECT 21.300 54.800 24.300 57.800 ;
    LAYER V1 ;
      RECT 26.800 54.800 29.800 57.800 ;
    LAYER V1 ;
      RECT 32.300 54.800 35.300 57.800 ;
  END
END NOR4
MACRO OR2
  CLASS CORE ;
  ORIGIN 0 0 ;
  SIZE 34.600 BY 75.600 ;
  SYMMETRY X Y ;
  SITE TR1um_access_site ;
  PIN VDD
    DIRECTION INOUT ;
    USE POWER ;
    PORT
      LAYER M1 ;
        RECT 5.000 41.000 29.600 57.600 ;
    END
  END VDD
  PIN GND
    DIRECTION INOUT ;
    USE GROUND ;
    PORT
      LAYER M1 ;
        RECT 5.000 0.000 29.600 9.800 ;
    END
  END GND
  PIN A
    DIRECTION INPUT ;
    USE SIGNAL ;
    PORT
      LAYER M2 ;
        RECT 15.600 16.100 19.000 19.500 ;
    END
  END A
  PIN B
    DIRECTION INPUT ;
    USE SIGNAL ;
    PORT
      LAYER M2 ;
        RECT 15.600 27.100 19.000 30.500 ;
    END
  END B
  PIN Y
    DIRECTION OUTPUT ;
    USE SIGNAL ;
    PORT
      LAYER M2 ;
        RECT 21.100 32.600 24.500 36.000 ;
    END
  END Y
  OBS
    LAYER M1 ;
      RECT 10.600 16.100 19.000 19.500 ;
    LAYER M1 ;
      RECT 14.400 27.100 19.000 35.200 ;
    LAYER M1 ;
      RECT 7.400 6.400 20.900 51.200 ;
    LAYER M1 ;
      RECT 13.100 41.000 15.700 51.200 ;
    LAYER M1 ;
      RECT 21.100 6.400 24.500 51.200 ;
    LAYER V1 ;
      RECT 4.800 0.000 7.800 2.800 ;
    LAYER V1 ;
      RECT 10.300 0.000 13.300 2.800 ;
    LAYER V1 ;
      RECT 15.800 0.000 18.800 2.800 ;
    LAYER V1 ;
      RECT 21.300 0.000 24.300 2.800 ;
    LAYER V1 ;
      RECT 26.800 0.000 29.800 2.800 ;
    LAYER V1 ;
      RECT 8.900 4.000 23.900 53.600 ;
    LAYER V1 ;
      RECT 4.800 54.800 7.800 57.800 ;
    LAYER V1 ;
      RECT 10.300 54.800 13.300 57.800 ;
    LAYER V1 ;
      RECT 15.800 54.800 18.800 57.800 ;
    LAYER V1 ;
      RECT 21.300 54.800 24.300 57.800 ;
    LAYER V1 ;
      RECT 26.800 54.800 29.800 57.800 ;
  END
END OR2
MACRO OR3
  CLASS CORE ;
  ORIGIN 0 0 ;
  SIZE 40.100 BY 75.600 ;
  SYMMETRY X Y ;
  SITE TR1um_access_site ;
  PIN VDD
    DIRECTION INOUT ;
    USE POWER ;
    PORT
      LAYER M1 ;
        RECT 5.000 41.000 35.100 57.600 ;
    END
  END VDD
  PIN GND
    DIRECTION INOUT ;
    USE GROUND ;
    PORT
      LAYER M1 ;
        RECT 5.000 0.000 35.100 9.800 ;
    END
  END GND
  PIN A
    DIRECTION INPUT ;
    USE SIGNAL ;
    PORT
      LAYER M2 ;
        RECT 15.600 16.100 19.000 19.500 ;
    END
  END A
  PIN B
    DIRECTION INPUT ;
    USE SIGNAL ;
    PORT
      LAYER M2 ;
        RECT 15.600 27.100 19.000 30.500 ;
    END
  END B
  PIN C
    DIRECTION INPUT ;
    USE SIGNAL ;
    PORT
      LAYER M2 ;
        RECT 21.100 21.600 24.500 25.000 ;
    END
  END C
  PIN Y
    DIRECTION OUTPUT ;
    USE SIGNAL ;
    PORT
      LAYER M2 ;
        RECT 26.600 32.600 30.000 36.000 ;
    END
  END Y
  OBS
    LAYER M1 ;
      RECT 12.600 16.100 19.000 23.900 ;
    LAYER M1 ;
      RECT 21.100 21.600 24.500 29.700 ;
    LAYER M1 ;
      RECT 10.400 27.100 19.000 35.700 ;
    LAYER M1 ;
      RECT 7.100 6.400 25.700 51.200 ;
    LAYER M1 ;
      RECT 13.100 41.000 15.700 51.200 ;
    LAYER M1 ;
      RECT 17.100 41.000 19.700 51.200 ;
    LAYER M1 ;
      RECT 25.100 6.400 30.000 51.200 ;
    LAYER V1 ;
      RECT 4.800 0.000 7.800 2.800 ;
    LAYER V1 ;
      RECT 10.300 0.000 13.300 2.800 ;
    LAYER V1 ;
      RECT 15.800 0.000 18.800 2.800 ;
    LAYER V1 ;
      RECT 21.300 0.000 24.300 2.800 ;
    LAYER V1 ;
      RECT 26.800 0.000 29.800 2.800 ;
    LAYER V1 ;
      RECT 32.300 0.000 35.300 2.800 ;
    LAYER V1 ;
      RECT 16.600 17.100 18.000 18.500 ;
    LAYER V1 ;
      RECT 16.600 28.100 18.000 29.500 ;
    LAYER V1 ;
      RECT 27.600 33.600 29.000 35.000 ;
    LAYER V1 ;
      RECT 8.700 4.000 29.200 53.600 ;
    LAYER V1 ;
      RECT 4.800 54.800 7.800 57.800 ;
    LAYER V1 ;
      RECT 10.300 54.800 13.300 57.800 ;
    LAYER V1 ;
      RECT 15.800 54.800 18.800 57.800 ;
    LAYER V1 ;
      RECT 21.300 54.800 24.300 57.800 ;
    LAYER V1 ;
      RECT 26.800 54.800 29.800 57.800 ;
    LAYER V1 ;
      RECT 32.300 54.800 35.300 57.800 ;
  END
END OR3
MACRO OR4
  CLASS CORE ;
  ORIGIN 0 0 ;
  SIZE 45.600 BY 75.600 ;
  SYMMETRY X Y ;
  SITE TR1um_access_site ;
  PIN VDD
    DIRECTION INOUT ;
    USE POWER ;
    PORT
      LAYER M1 ;
        RECT 5.000 41.000 40.600 57.600 ;
    END
  END VDD
  PIN GND
    DIRECTION INOUT ;
    USE GROUND ;
    PORT
      LAYER M1 ;
        RECT 5.000 0.000 40.600 9.800 ;
    END
  END GND
  PIN A
    DIRECTION INPUT ;
    USE SIGNAL ;
    PORT
      LAYER M2 ;
        RECT 21.100 21.600 24.500 25.000 ;
    END
  END A
  PIN B
    DIRECTION INPUT ;
    USE SIGNAL ;
    PORT
      LAYER M2 ;
        RECT 21.100 32.600 24.500 36.000 ;
    END
  END B
  PIN C
    DIRECTION INPUT ;
    USE SIGNAL ;
    PORT
      LAYER M2 ;
        RECT 15.600 16.100 19.000 19.500 ;
    END
  END C
  PIN D
    DIRECTION INPUT ;
    USE SIGNAL ;
    PORT
      LAYER M2 ;
        RECT 15.600 27.100 19.000 30.500 ;
    END
  END D
  PIN Y
    DIRECTION OUTPUT ;
    USE SIGNAL ;
    PORT
      LAYER M2 ;
        RECT 26.600 27.100 30.000 30.500 ;
    END
  END Y
  OBS
    LAYER M1 ;
      RECT 12.000 14.600 19.000 19.500 ;
    LAYER M1 ;
      RECT 21.100 21.600 27.600 25.000 ;
    LAYER M1 ;
      RECT 10.700 27.100 19.000 35.800 ;
    LAYER M1 ;
      RECT 18.100 32.600 24.500 36.000 ;
    LAYER M1 ;
      RECT 7.300 6.400 27.700 51.200 ;
    LAYER M1 ;
      RECT 13.100 41.000 15.700 51.200 ;
    LAYER M1 ;
      RECT 17.100 41.000 19.700 51.200 ;
    LAYER M1 ;
      RECT 21.100 41.000 23.700 51.200 ;
    LAYER M1 ;
      RECT 26.600 6.400 31.700 51.200 ;
    LAYER V1 ;
      RECT 4.800 0.000 7.800 2.800 ;
    LAYER V1 ;
      RECT 10.300 0.000 13.300 2.800 ;
    LAYER V1 ;
      RECT 15.800 0.000 18.800 2.800 ;
    LAYER V1 ;
      RECT 21.300 0.000 24.300 2.800 ;
    LAYER V1 ;
      RECT 26.800 0.000 29.800 2.800 ;
    LAYER V1 ;
      RECT 32.300 0.000 35.300 2.800 ;
    LAYER V1 ;
      RECT 37.800 0.000 40.800 2.800 ;
    LAYER V1 ;
      RECT 16.600 17.100 18.000 18.500 ;
    LAYER V1 ;
      RECT 22.100 22.600 23.500 24.000 ;
    LAYER V1 ;
      RECT 16.600 28.100 18.000 29.500 ;
    LAYER V1 ;
      RECT 27.600 28.100 29.000 29.500 ;
    LAYER V1 ;
      RECT 22.100 33.600 23.500 35.000 ;
    LAYER V1 ;
      RECT 7.100 4.000 33.400 53.600 ;
    LAYER V1 ;
      RECT 4.800 54.800 7.800 57.800 ;
    LAYER V1 ;
      RECT 10.300 54.800 13.300 57.800 ;
    LAYER V1 ;
      RECT 15.800 54.800 18.800 57.800 ;
    LAYER V1 ;
      RECT 21.300 54.800 24.300 57.800 ;
    LAYER V1 ;
      RECT 26.800 54.800 29.800 57.800 ;
    LAYER V1 ;
      RECT 32.300 54.800 35.300 57.800 ;
    LAYER V1 ;
      RECT 37.800 54.800 40.800 57.800 ;
  END
END OR4
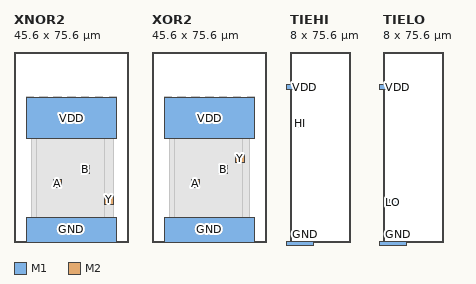
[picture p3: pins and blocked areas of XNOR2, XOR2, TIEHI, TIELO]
MACRO XNOR2
  CLASS CORE ;
  ORIGIN 0 0 ;
  SIZE 45.600 BY 75.600 ;
  SYMMETRY X Y ;
  SITE TR1um_access_site ;
  PIN VDD
    DIRECTION INOUT ;
    USE POWER ;
    PORT
      LAYER M1 ;
        RECT 5.000 41.000 40.600 57.600 ;
    END
  END VDD
  PIN GND
    DIRECTION INOUT ;
    USE GROUND ;
    PORT
      LAYER M1 ;
        RECT 5.000 0.000 40.600 9.800 ;
    END
  END GND
  PIN A
    DIRECTION INPUT ;
    USE SIGNAL ;
    PORT
      LAYER M2 ;
        RECT 15.600 21.600 19.000 25.000 ;
    END
  END A
  PIN B
    DIRECTION INPUT ;
    USE SIGNAL ;
    PORT
      LAYER M2 ;
        RECT 26.600 27.100 30.000 30.500 ;
    END
  END B
  PIN Y
    DIRECTION OUTPUT ;
    USE SIGNAL ;
    PORT
      LAYER M2 ;
        RECT 36.200 15.100 39.600 18.500 ;
    END
  END Y
  OBS
    LAYER M1 ;
      RECT 13.100 6.400 15.700 9.800 ;
    LAYER M1 ;
      RECT 25.100 6.400 35.700 13.600 ;
    LAYER M1 ;
      RECT 10.300 19.000 32.900 25.000 ;
    LAYER M1 ;
      RECT 15.900 23.800 30.000 30.500 ;
    LAYER M1 ;
      RECT 7.000 6.400 19.700 51.200 ;
    LAYER M1 ;
      RECT 29.100 41.000 31.700 51.200 ;
    LAYER M1 ;
      RECT 21.100 6.400 39.600 51.200 ;
    LAYER V1 ;
      RECT 4.800 0.000 7.800 2.800 ;
    LAYER V1 ;
      RECT 10.300 0.000 13.300 2.800 ;
    LAYER V1 ;
      RECT 15.800 0.000 18.800 2.800 ;
    LAYER V1 ;
      RECT 21.300 0.000 24.300 2.800 ;
    LAYER V1 ;
      RECT 26.800 0.000 29.800 2.800 ;
    LAYER V1 ;
      RECT 32.300 0.000 35.300 2.800 ;
    LAYER V1 ;
      RECT 37.800 0.000 40.800 2.800 ;
    LAYER V1 ;
      RECT 37.200 16.100 38.600 17.500 ;
    LAYER V1 ;
      RECT 16.600 22.600 18.000 24.000 ;
    LAYER V1 ;
      RECT 27.600 28.100 29.000 29.500 ;
    LAYER V1 ;
      RECT 8.900 4.000 35.900 53.600 ;
    LAYER V1 ;
      RECT 4.800 54.800 7.800 57.800 ;
    LAYER V1 ;
      RECT 10.300 54.800 13.300 57.800 ;
    LAYER V1 ;
      RECT 15.800 54.800 18.800 57.800 ;
    LAYER V1 ;
      RECT 21.300 54.800 24.300 57.800 ;
    LAYER V1 ;
      RECT 26.800 54.800 29.800 57.800 ;
    LAYER V1 ;
      RECT 32.300 54.800 35.300 57.800 ;
    LAYER V1 ;
      RECT 37.800 54.800 40.800 57.800 ;
  END
END XNOR2
MACRO XOR2
  CLASS CORE ;
  ORIGIN 0 0 ;
  SIZE 45.600 BY 75.600 ;
  SYMMETRY X Y ;
  SITE TR1um_access_site ;
  PIN VDD
    DIRECTION INOUT ;
    USE POWER ;
    PORT
      LAYER M1 ;
        RECT 5.000 41.000 40.600 57.600 ;
    END
  END VDD
  PIN GND
    DIRECTION INOUT ;
    USE GROUND ;
    PORT
      LAYER M1 ;
        RECT 5.000 0.000 40.600 9.800 ;
    END
  END GND
  PIN A
    DIRECTION INPUT ;
    USE SIGNAL ;
    PORT
      LAYER M2 ;
        RECT 15.600 21.600 19.000 25.000 ;
    END
  END A
  PIN B
    DIRECTION INPUT ;
    USE SIGNAL ;
    PORT
      LAYER M2 ;
        RECT 26.600 27.100 30.000 30.500 ;
    END
  END B
  PIN Y
    DIRECTION OUTPUT ;
    USE SIGNAL ;
    PORT
      LAYER M2 ;
        RECT 33.400 31.600 36.800 35.000 ;
    END
  END Y
  OBS
    LAYER M1 ;
      RECT 29.100 6.400 31.700 9.800 ;
    LAYER M1 ;
      RECT 10.300 19.000 32.900 25.000 ;
    LAYER M1 ;
      RECT 15.900 23.800 30.000 30.500 ;
    LAYER M1 ;
      RECT 13.100 41.000 15.700 51.200 ;
    LAYER M1 ;
      RECT 7.000 6.400 19.700 51.200 ;
    LAYER M1 ;
      RECT 21.100 6.400 38.600 51.200 ;
    LAYER M1 ;
      RECT 25.100 37.400 35.700 51.200 ;
    LAYER V1 ;
      RECT 4.800 0.000 7.800 2.800 ;
    LAYER V1 ;
      RECT 10.300 0.000 13.300 2.800 ;
    LAYER V1 ;
      RECT 15.800 0.000 18.800 2.800 ;
    LAYER V1 ;
      RECT 21.300 0.000 24.300 2.800 ;
    LAYER V1 ;
      RECT 26.800 0.000 29.800 2.800 ;
    LAYER V1 ;
      RECT 32.300 0.000 35.300 2.800 ;
    LAYER V1 ;
      RECT 37.800 0.000 40.800 2.800 ;
    LAYER V1 ;
      RECT 16.600 22.600 18.000 24.000 ;
    LAYER V1 ;
      RECT 27.600 28.100 29.000 29.500 ;
    LAYER V1 ;
      RECT 34.400 32.600 35.800 34.000 ;
    LAYER V1 ;
      RECT 8.900 4.000 35.900 53.600 ;
    LAYER V1 ;
      RECT 4.800 54.800 7.800 57.800 ;
    LAYER V1 ;
      RECT 10.300 54.800 13.300 57.800 ;
    LAYER V1 ;
      RECT 15.800 54.800 18.800 57.800 ;
    LAYER V1 ;
      RECT 21.300 54.800 24.300 57.800 ;
    LAYER V1 ;
      RECT 26.800 54.800 29.800 57.800 ;
    LAYER V1 ;
      RECT 32.300 54.800 35.300 57.800 ;
    LAYER V1 ;
      RECT 37.800 54.800 40.800 57.800 ;
  END
END XOR2
MACRO TIEHI
  CLASS CORE ;
  SITE TR1um_access_site ;
  ORIGIN 0 0 ;
  SIZE 8.000 BY 75.600 ;
  PIN HI
    DIRECTION OUTPUT ;
    USE SIGNAL ;
    PORT
      LAYER M1 ;
        RECT 2.500 45.500 5.500 48.500 ;
    END
  END HI
  PIN VDD
    DIRECTION INOUT ;
    USE POWER ;
    PORT
      LAYER M1 ;
        RECT -1.300 60.600 9.300 62.600 ;
    END
  END VDD
  PIN GND
    DIRECTION INOUT ;
    USE GROUND ;
    PORT
      LAYER M1 ;
        RECT -1.300 -1.300 9.300 0.300 ;
    END
  END GND
END TIEHI
MACRO TIELO
  CLASS CORE ;
  SITE TR1um_access_site ;
  ORIGIN 0 0 ;
  SIZE 8.000 BY 75.600 ;
  PIN LO
    DIRECTION OUTPUT ;
    USE SIGNAL ;
    PORT
      LAYER M1 ;
        RECT 2.500 14.100 5.500 17.100 ;
    END
  END LO
  PIN VDD
    DIRECTION INOUT ;
    USE POWER ;
    PORT
      LAYER M1 ;
        RECT -1.300 60.600 9.300 62.600 ;
    END
  END VDD
  PIN GND
    DIRECTION INOUT ;
    USE GROUND ;
    PORT
      LAYER M1 ;
        RECT -1.300 -1.300 9.300 0.300 ;
    END
  END GND
END TIELO
